VERSION 5.8 ;
BUSBITCHARS "[]" ;
DIVIDERCHAR "/" ;
UNITS
    DATABASE MICRONS 1000 ;
END UNITS

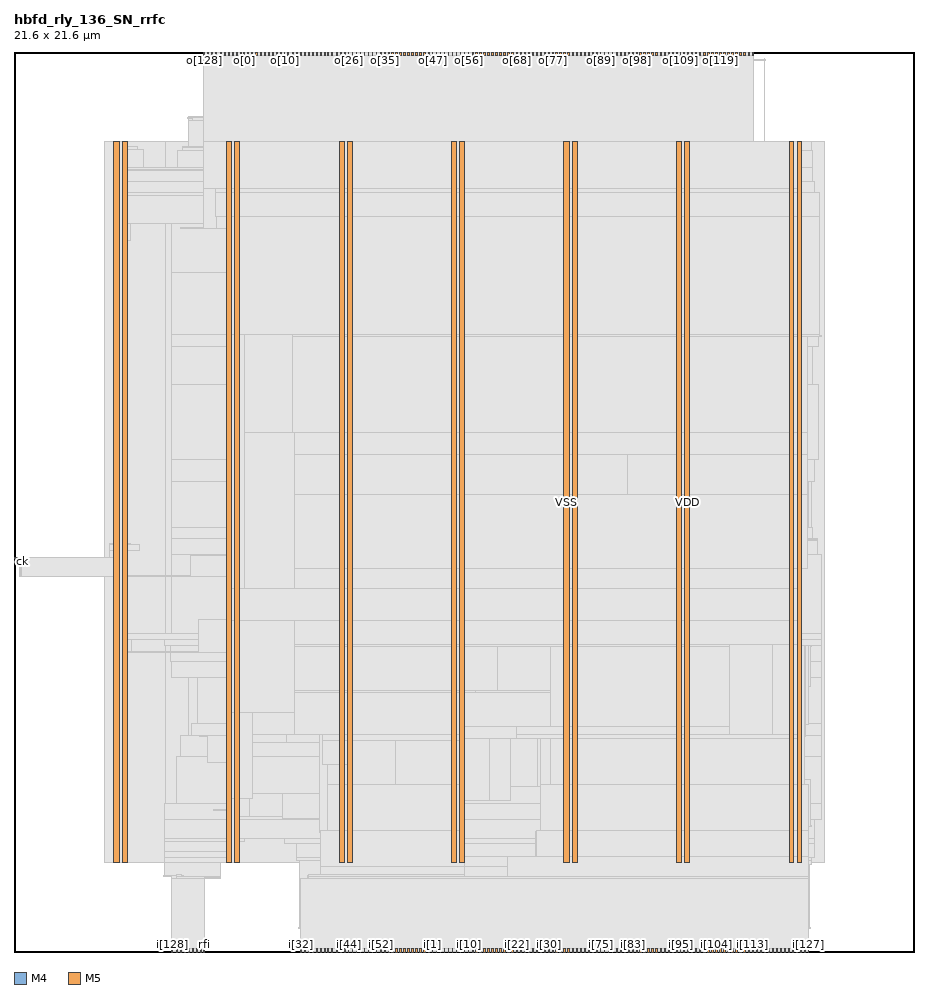
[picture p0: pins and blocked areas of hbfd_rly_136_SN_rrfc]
MACRO hbfd_rly_136_SN_rrfc
  FOREIGN hbfd_rly_136_SN_rrfc 0 0 ;
  CLASS BLOCK ;
  SIZE 21.6 BY 21.6 ;
  PIN ck
    DIRECTION INPUT ;
    USE SIGNAL ;
    PORT
      LAYER M4 ;
        RECT  0 9.36 0.084 9.384 ;
    END
  END ck
  PIN i[0]
    DIRECTION INPUT ;
    USE SIGNAL ;
    PORT
      LAYER M5 ;
        RECT  9.936 0 9.96 0.084 ;
    END
  END i[0]
  PIN i[100]
    DIRECTION INPUT ;
    USE SIGNAL ;
    PORT
      LAYER M5 ;
        RECT  16.464 0 16.488 0.084 ;
    END
  END i[100]
  PIN i[101]
    DIRECTION INPUT ;
    USE SIGNAL ;
    PORT
      LAYER M5 ;
        RECT  16.56 0 16.584 0.084 ;
    END
  END i[101]
  PIN i[102]
    DIRECTION INPUT ;
    USE SIGNAL ;
    PORT
      LAYER M5 ;
        RECT  16.656 0 16.68 0.084 ;
    END
  END i[102]
  PIN i[103]
    DIRECTION INPUT ;
    USE SIGNAL ;
    PORT
      LAYER M5 ;
        RECT  16.752 0 16.776 0.084 ;
    END
  END i[103]
  PIN i[104]
    DIRECTION INPUT ;
    USE SIGNAL ;
    PORT
      LAYER M5 ;
        RECT  16.848 0 16.872 0.084 ;
    END
  END i[104]
  PIN i[105]
    DIRECTION INPUT ;
    USE SIGNAL ;
    PORT
      LAYER M5 ;
        RECT  16.944 0 16.968 0.084 ;
    END
  END i[105]
  PIN i[106]
    DIRECTION INPUT ;
    USE SIGNAL ;
    PORT
      LAYER M5 ;
        RECT  17.04 0 17.064 0.084 ;
    END
  END i[106]
  PIN i[107]
    DIRECTION INPUT ;
    USE SIGNAL ;
    PORT
      LAYER M5 ;
        RECT  17.136 0 17.16 0.084 ;
    END
  END i[107]
  PIN i[108]
    DIRECTION INPUT ;
    USE SIGNAL ;
    PORT
      LAYER M5 ;
        RECT  17.232 0 17.256 0.084 ;
    END
  END i[108]
  PIN i[109]
    DIRECTION INPUT ;
    USE SIGNAL ;
    PORT
      LAYER M5 ;
        RECT  17.328 0 17.352 0.084 ;
    END
  END i[109]
  PIN i[10]
    DIRECTION INPUT ;
    USE SIGNAL ;
    PORT
      LAYER M5 ;
        RECT  10.896 0 10.92 0.084 ;
    END
  END i[10]
  PIN i[110]
    DIRECTION INPUT ;
    USE SIGNAL ;
    PORT
      LAYER M5 ;
        RECT  17.424 0 17.448 0.084 ;
    END
  END i[110]
  PIN i[111]
    DIRECTION INPUT ;
    USE SIGNAL ;
    PORT
      LAYER M5 ;
        RECT  17.52 0 17.544 0.084 ;
    END
  END i[111]
  PIN i[112]
    DIRECTION INPUT ;
    USE SIGNAL ;
    PORT
      LAYER M5 ;
        RECT  17.616 0 17.64 0.084 ;
    END
  END i[112]
  PIN i[113]
    DIRECTION INPUT ;
    USE SIGNAL ;
    PORT
      LAYER M5 ;
        RECT  17.712 0 17.736 0.084 ;
    END
  END i[113]
  PIN i[114]
    DIRECTION INPUT ;
    USE SIGNAL ;
    PORT
      LAYER M5 ;
        RECT  17.808 0 17.832 0.084 ;
    END
  END i[114]
  PIN i[115]
    DIRECTION INPUT ;
    USE SIGNAL ;
    PORT
      LAYER M5 ;
        RECT  17.904 0 17.928 0.084 ;
    END
  END i[115]
  PIN i[116]
    DIRECTION INPUT ;
    USE SIGNAL ;
    PORT
      LAYER M5 ;
        RECT  18 0 18.024 0.084 ;
    END
  END i[116]
  PIN i[117]
    DIRECTION INPUT ;
    USE SIGNAL ;
    PORT
      LAYER M5 ;
        RECT  18.096 0 18.12 0.084 ;
    END
  END i[117]
  PIN i[118]
    DIRECTION INPUT ;
    USE SIGNAL ;
    PORT
      LAYER M5 ;
        RECT  18.192 0 18.216 0.084 ;
    END
  END i[118]
  PIN i[119]
    DIRECTION INPUT ;
    USE SIGNAL ;
    PORT
      LAYER M5 ;
        RECT  18.288 0 18.312 0.084 ;
    END
  END i[119]
  PIN i[11]
    DIRECTION INPUT ;
    USE SIGNAL ;
    PORT
      LAYER M5 ;
        RECT  10.992 0 11.016 0.084 ;
    END
  END i[11]
  PIN i[120]
    DIRECTION INPUT ;
    USE SIGNAL ;
    PORT
      LAYER M5 ;
        RECT  18.384 0 18.408 0.084 ;
    END
  END i[120]
  PIN i[121]
    DIRECTION INPUT ;
    USE SIGNAL ;
    PORT
      LAYER M5 ;
        RECT  18.48 0 18.504 0.084 ;
    END
  END i[121]
  PIN i[122]
    DIRECTION INPUT ;
    USE SIGNAL ;
    PORT
      LAYER M5 ;
        RECT  18.576 0 18.6 0.084 ;
    END
  END i[122]
  PIN i[123]
    DIRECTION INPUT ;
    USE SIGNAL ;
    PORT
      LAYER M5 ;
        RECT  18.672 0 18.696 0.084 ;
    END
  END i[123]
  PIN i[124]
    DIRECTION INPUT ;
    USE SIGNAL ;
    PORT
      LAYER M5 ;
        RECT  18.768 0 18.792 0.084 ;
    END
  END i[124]
  PIN i[125]
    DIRECTION INPUT ;
    USE SIGNAL ;
    PORT
      LAYER M5 ;
        RECT  18.864 0 18.888 0.084 ;
    END
  END i[125]
  PIN i[126]
    DIRECTION INPUT ;
    USE SIGNAL ;
    PORT
      LAYER M5 ;
        RECT  18.96 0 18.984 0.084 ;
    END
  END i[126]
  PIN i[127]
    DIRECTION INPUT ;
    USE SIGNAL ;
    PORT
      LAYER M5 ;
        RECT  19.056 0 19.08 0.084 ;
    END
  END i[127]
  PIN i[128]
    DIRECTION INPUT ;
    USE SIGNAL ;
    PORT
      LAYER M5 ;
        RECT  3.792 0 3.816 0.084 ;
    END
  END i[128]
  PIN i[129]
    DIRECTION INPUT ;
    USE SIGNAL ;
    PORT
      LAYER M5 ;
        RECT  3.888 0 3.912 0.084 ;
    END
  END i[129]
  PIN i[12]
    DIRECTION INPUT ;
    USE SIGNAL ;
    PORT
      LAYER M5 ;
        RECT  11.088 0 11.112 0.084 ;
    END
  END i[12]
  PIN i[130]
    DIRECTION INPUT ;
    USE SIGNAL ;
    PORT
      LAYER M5 ;
        RECT  3.984 0 4.008 0.084 ;
    END
  END i[130]
  PIN i[131]
    DIRECTION INPUT ;
    USE SIGNAL ;
    PORT
      LAYER M5 ;
        RECT  4.08 0 4.104 0.084 ;
    END
  END i[131]
  PIN i[132]
    DIRECTION INPUT ;
    USE SIGNAL ;
    PORT
      LAYER M5 ;
        RECT  4.176 0 4.2 0.084 ;
    END
  END i[132]
  PIN i[133]
    DIRECTION INPUT ;
    USE SIGNAL ;
    PORT
      LAYER M5 ;
        RECT  4.272 0 4.296 0.084 ;
    END
  END i[133]
  PIN i[134]
    DIRECTION INPUT ;
    USE SIGNAL ;
    PORT
      LAYER M5 ;
        RECT  4.368 0 4.392 0.084 ;
    END
  END i[134]
  PIN i[135]
    DIRECTION INPUT ;
    USE SIGNAL ;
    PORT
      LAYER M5 ;
        RECT  4.464 0 4.488 0.084 ;
    END
  END i[135]
  PIN i[13]
    DIRECTION INPUT ;
    USE SIGNAL ;
    PORT
      LAYER M5 ;
        RECT  11.184 0 11.208 0.084 ;
    END
  END i[13]
  PIN i[14]
    DIRECTION INPUT ;
    USE SIGNAL ;
    PORT
      LAYER M5 ;
        RECT  11.28 0 11.304 0.084 ;
    END
  END i[14]
  PIN i[15]
    DIRECTION INPUT ;
    USE SIGNAL ;
    PORT
      LAYER M5 ;
        RECT  11.376 0 11.4 0.084 ;
    END
  END i[15]
  PIN i[16]
    DIRECTION INPUT ;
    USE SIGNAL ;
    PORT
      LAYER M5 ;
        RECT  11.472 0 11.496 0.084 ;
    END
  END i[16]
  PIN i[17]
    DIRECTION INPUT ;
    USE SIGNAL ;
    PORT
      LAYER M5 ;
        RECT  11.568 0 11.592 0.084 ;
    END
  END i[17]
  PIN i[18]
    DIRECTION INPUT ;
    USE SIGNAL ;
    PORT
      LAYER M5 ;
        RECT  11.664 0 11.688 0.084 ;
    END
  END i[18]
  PIN i[19]
    DIRECTION INPUT ;
    USE SIGNAL ;
    PORT
      LAYER M5 ;
        RECT  11.76 0 11.784 0.084 ;
    END
  END i[19]
  PIN i[1]
    DIRECTION INPUT ;
    USE SIGNAL ;
    PORT
      LAYER M5 ;
        RECT  10.032 0 10.056 0.084 ;
    END
  END i[1]
  PIN i[20]
    DIRECTION INPUT ;
    USE SIGNAL ;
    PORT
      LAYER M5 ;
        RECT  11.856 0 11.88 0.084 ;
    END
  END i[20]
  PIN i[21]
    DIRECTION INPUT ;
    USE SIGNAL ;
    PORT
      LAYER M5 ;
        RECT  11.952 0 11.976 0.084 ;
    END
  END i[21]
  PIN i[22]
    DIRECTION INPUT ;
    USE SIGNAL ;
    PORT
      LAYER M5 ;
        RECT  12.048 0 12.072 0.084 ;
    END
  END i[22]
  PIN i[23]
    DIRECTION INPUT ;
    USE SIGNAL ;
    PORT
      LAYER M5 ;
        RECT  12.144 0 12.168 0.084 ;
    END
  END i[23]
  PIN i[24]
    DIRECTION INPUT ;
    USE SIGNAL ;
    PORT
      LAYER M5 ;
        RECT  12.24 0 12.264 0.084 ;
    END
  END i[24]
  PIN i[25]
    DIRECTION INPUT ;
    USE SIGNAL ;
    PORT
      LAYER M5 ;
        RECT  12.336 0 12.36 0.084 ;
    END
  END i[25]
  PIN i[26]
    DIRECTION INPUT ;
    USE SIGNAL ;
    PORT
      LAYER M5 ;
        RECT  12.432 0 12.456 0.084 ;
    END
  END i[26]
  PIN i[27]
    DIRECTION INPUT ;
    USE SIGNAL ;
    PORT
      LAYER M5 ;
        RECT  12.528 0 12.552 0.084 ;
    END
  END i[27]
  PIN i[28]
    DIRECTION INPUT ;
    USE SIGNAL ;
    PORT
      LAYER M5 ;
        RECT  12.624 0 12.648 0.084 ;
    END
  END i[28]
  PIN i[29]
    DIRECTION INPUT ;
    USE SIGNAL ;
    PORT
      LAYER M5 ;
        RECT  12.72 0 12.744 0.084 ;
    END
  END i[29]
  PIN i[2]
    DIRECTION INPUT ;
    USE SIGNAL ;
    PORT
      LAYER M5 ;
        RECT  10.128 0 10.152 0.084 ;
    END
  END i[2]
  PIN i[30]
    DIRECTION INPUT ;
    USE SIGNAL ;
    PORT
      LAYER M5 ;
        RECT  12.816 0 12.84 0.084 ;
    END
  END i[30]
  PIN i[31]
    DIRECTION INPUT ;
    USE SIGNAL ;
    PORT
      LAYER M5 ;
        RECT  12.912 0 12.936 0.084 ;
    END
  END i[31]
  PIN i[32]
    DIRECTION INPUT ;
    USE SIGNAL ;
    PORT
      LAYER M5 ;
        RECT  6.864 0 6.888 0.084 ;
    END
  END i[32]
  PIN i[33]
    DIRECTION INPUT ;
    USE SIGNAL ;
    PORT
      LAYER M5 ;
        RECT  6.96 0 6.984 0.084 ;
    END
  END i[33]
  PIN i[34]
    DIRECTION INPUT ;
    USE SIGNAL ;
    PORT
      LAYER M5 ;
        RECT  7.056 0 7.08 0.084 ;
    END
  END i[34]
  PIN i[35]
    DIRECTION INPUT ;
    USE SIGNAL ;
    PORT
      LAYER M5 ;
        RECT  7.152 0 7.176 0.084 ;
    END
  END i[35]
  PIN i[36]
    DIRECTION INPUT ;
    USE SIGNAL ;
    PORT
      LAYER M5 ;
        RECT  7.248 0 7.272 0.084 ;
    END
  END i[36]
  PIN i[37]
    DIRECTION INPUT ;
    USE SIGNAL ;
    PORT
      LAYER M5 ;
        RECT  7.344 0 7.368 0.084 ;
    END
  END i[37]
  PIN i[38]
    DIRECTION INPUT ;
    USE SIGNAL ;
    PORT
      LAYER M5 ;
        RECT  7.44 0 7.464 0.084 ;
    END
  END i[38]
  PIN i[39]
    DIRECTION INPUT ;
    USE SIGNAL ;
    PORT
      LAYER M5 ;
        RECT  7.536 0 7.56 0.084 ;
    END
  END i[39]
  PIN i[3]
    DIRECTION INPUT ;
    USE SIGNAL ;
    PORT
      LAYER M5 ;
        RECT  10.224 0 10.248 0.084 ;
    END
  END i[3]
  PIN i[40]
    DIRECTION INPUT ;
    USE SIGNAL ;
    PORT
      LAYER M5 ;
        RECT  7.632 0 7.656 0.084 ;
    END
  END i[40]
  PIN i[41]
    DIRECTION INPUT ;
    USE SIGNAL ;
    PORT
      LAYER M5 ;
        RECT  7.728 0 7.752 0.084 ;
    END
  END i[41]
  PIN i[42]
    DIRECTION INPUT ;
    USE SIGNAL ;
    PORT
      LAYER M5 ;
        RECT  7.824 0 7.848 0.084 ;
    END
  END i[42]
  PIN i[43]
    DIRECTION INPUT ;
    USE SIGNAL ;
    PORT
      LAYER M5 ;
        RECT  7.92 0 7.944 0.084 ;
    END
  END i[43]
  PIN i[44]
    DIRECTION INPUT ;
    USE SIGNAL ;
    PORT
      LAYER M5 ;
        RECT  8.016 0 8.04 0.084 ;
    END
  END i[44]
  PIN i[45]
    DIRECTION INPUT ;
    USE SIGNAL ;
    PORT
      LAYER M5 ;
        RECT  8.112 0 8.136 0.084 ;
    END
  END i[45]
  PIN i[46]
    DIRECTION INPUT ;
    USE SIGNAL ;
    PORT
      LAYER M5 ;
        RECT  8.208 0 8.232 0.084 ;
    END
  END i[46]
  PIN i[47]
    DIRECTION INPUT ;
    USE SIGNAL ;
    PORT
      LAYER M5 ;
        RECT  8.304 0 8.328 0.084 ;
    END
  END i[47]
  PIN i[48]
    DIRECTION INPUT ;
    USE SIGNAL ;
    PORT
      LAYER M5 ;
        RECT  8.4 0 8.424 0.084 ;
    END
  END i[48]
  PIN i[49]
    DIRECTION INPUT ;
    USE SIGNAL ;
    PORT
      LAYER M5 ;
        RECT  8.496 0 8.52 0.084 ;
    END
  END i[49]
  PIN i[4]
    DIRECTION INPUT ;
    USE SIGNAL ;
    PORT
      LAYER M5 ;
        RECT  10.32 0 10.344 0.084 ;
    END
  END i[4]
  PIN i[50]
    DIRECTION INPUT ;
    USE SIGNAL ;
    PORT
      LAYER M5 ;
        RECT  8.592 0 8.616 0.084 ;
    END
  END i[50]
  PIN i[51]
    DIRECTION INPUT ;
    USE SIGNAL ;
    PORT
      LAYER M5 ;
        RECT  8.688 0 8.712 0.084 ;
    END
  END i[51]
  PIN i[52]
    DIRECTION INPUT ;
    USE SIGNAL ;
    PORT
      LAYER M5 ;
        RECT  8.784 0 8.808 0.084 ;
    END
  END i[52]
  PIN i[53]
    DIRECTION INPUT ;
    USE SIGNAL ;
    PORT
      LAYER M5 ;
        RECT  8.88 0 8.904 0.084 ;
    END
  END i[53]
  PIN i[54]
    DIRECTION INPUT ;
    USE SIGNAL ;
    PORT
      LAYER M5 ;
        RECT  8.976 0 9 0.084 ;
    END
  END i[54]
  PIN i[55]
    DIRECTION INPUT ;
    USE SIGNAL ;
    PORT
      LAYER M5 ;
        RECT  9.072 0 9.096 0.084 ;
    END
  END i[55]
  PIN i[56]
    DIRECTION INPUT ;
    USE SIGNAL ;
    PORT
      LAYER M5 ;
        RECT  9.168 0 9.192 0.084 ;
    END
  END i[56]
  PIN i[57]
    DIRECTION INPUT ;
    USE SIGNAL ;
    PORT
      LAYER M5 ;
        RECT  9.264 0 9.288 0.084 ;
    END
  END i[57]
  PIN i[58]
    DIRECTION INPUT ;
    USE SIGNAL ;
    PORT
      LAYER M5 ;
        RECT  9.36 0 9.384 0.084 ;
    END
  END i[58]
  PIN i[59]
    DIRECTION INPUT ;
    USE SIGNAL ;
    PORT
      LAYER M5 ;
        RECT  9.456 0 9.48 0.084 ;
    END
  END i[59]
  PIN i[5]
    DIRECTION INPUT ;
    USE SIGNAL ;
    PORT
      LAYER M5 ;
        RECT  10.416 0 10.44 0.084 ;
    END
  END i[5]
  PIN i[60]
    DIRECTION INPUT ;
    USE SIGNAL ;
    PORT
      LAYER M5 ;
        RECT  9.552 0 9.576 0.084 ;
    END
  END i[60]
  PIN i[61]
    DIRECTION INPUT ;
    USE SIGNAL ;
    PORT
      LAYER M5 ;
        RECT  9.648 0 9.672 0.084 ;
    END
  END i[61]
  PIN i[62]
    DIRECTION INPUT ;
    USE SIGNAL ;
    PORT
      LAYER M5 ;
        RECT  9.744 0 9.768 0.084 ;
    END
  END i[62]
  PIN i[63]
    DIRECTION INPUT ;
    USE SIGNAL ;
    PORT
      LAYER M5 ;
        RECT  9.84 0 9.864 0.084 ;
    END
  END i[63]
  PIN i[64]
    DIRECTION INPUT ;
    USE SIGNAL ;
    PORT
      LAYER M5 ;
        RECT  13.008 0 13.032 0.084 ;
    END
  END i[64]
  PIN i[65]
    DIRECTION INPUT ;
    USE SIGNAL ;
    PORT
      LAYER M5 ;
        RECT  13.104 0 13.128 0.084 ;
    END
  END i[65]
  PIN i[66]
    DIRECTION INPUT ;
    USE SIGNAL ;
    PORT
      LAYER M5 ;
        RECT  13.2 0 13.224 0.084 ;
    END
  END i[66]
  PIN i[67]
    DIRECTION INPUT ;
    USE SIGNAL ;
    PORT
      LAYER M5 ;
        RECT  13.296 0 13.32 0.084 ;
    END
  END i[67]
  PIN i[68]
    DIRECTION INPUT ;
    USE SIGNAL ;
    PORT
      LAYER M5 ;
        RECT  13.392 0 13.416 0.084 ;
    END
  END i[68]
  PIN i[69]
    DIRECTION INPUT ;
    USE SIGNAL ;
    PORT
      LAYER M5 ;
        RECT  13.488 0 13.512 0.084 ;
    END
  END i[69]
  PIN i[6]
    DIRECTION INPUT ;
    USE SIGNAL ;
    PORT
      LAYER M5 ;
        RECT  10.512 0 10.536 0.084 ;
    END
  END i[6]
  PIN i[70]
    DIRECTION INPUT ;
    USE SIGNAL ;
    PORT
      LAYER M5 ;
        RECT  13.584 0 13.608 0.084 ;
    END
  END i[70]
  PIN i[71]
    DIRECTION INPUT ;
    USE SIGNAL ;
    PORT
      LAYER M5 ;
        RECT  13.68 0 13.704 0.084 ;
    END
  END i[71]
  PIN i[72]
    DIRECTION INPUT ;
    USE SIGNAL ;
    PORT
      LAYER M5 ;
        RECT  13.776 0 13.8 0.084 ;
    END
  END i[72]
  PIN i[73]
    DIRECTION INPUT ;
    USE SIGNAL ;
    PORT
      LAYER M5 ;
        RECT  13.872 0 13.896 0.084 ;
    END
  END i[73]
  PIN i[74]
    DIRECTION INPUT ;
    USE SIGNAL ;
    PORT
      LAYER M5 ;
        RECT  13.968 0 13.992 0.084 ;
    END
  END i[74]
  PIN i[75]
    DIRECTION INPUT ;
    USE SIGNAL ;
    PORT
      LAYER M5 ;
        RECT  14.064 0 14.088 0.084 ;
    END
  END i[75]
  PIN i[76]
    DIRECTION INPUT ;
    USE SIGNAL ;
    PORT
      LAYER M5 ;
        RECT  14.16 0 14.184 0.084 ;
    END
  END i[76]
  PIN i[77]
    DIRECTION INPUT ;
    USE SIGNAL ;
    PORT
      LAYER M5 ;
        RECT  14.256 0 14.28 0.084 ;
    END
  END i[77]
  PIN i[78]
    DIRECTION INPUT ;
    USE SIGNAL ;
    PORT
      LAYER M5 ;
        RECT  14.352 0 14.376 0.084 ;
    END
  END i[78]
  PIN i[79]
    DIRECTION INPUT ;
    USE SIGNAL ;
    PORT
      LAYER M5 ;
        RECT  14.448 0 14.472 0.084 ;
    END
  END i[79]
  PIN i[7]
    DIRECTION INPUT ;
    USE SIGNAL ;
    PORT
      LAYER M5 ;
        RECT  10.608 0 10.632 0.084 ;
    END
  END i[7]
  PIN i[80]
    DIRECTION INPUT ;
    USE SIGNAL ;
    PORT
      LAYER M5 ;
        RECT  14.544 0 14.568 0.084 ;
    END
  END i[80]
  PIN i[81]
    DIRECTION INPUT ;
    USE SIGNAL ;
    PORT
      LAYER M5 ;
        RECT  14.64 0 14.664 0.084 ;
    END
  END i[81]
  PIN i[82]
    DIRECTION INPUT ;
    USE SIGNAL ;
    PORT
      LAYER M5 ;
        RECT  14.736 0 14.76 0.084 ;
    END
  END i[82]
  PIN i[83]
    DIRECTION INPUT ;
    USE SIGNAL ;
    PORT
      LAYER M5 ;
        RECT  14.832 0 14.856 0.084 ;
    END
  END i[83]
  PIN i[84]
    DIRECTION INPUT ;
    USE SIGNAL ;
    PORT
      LAYER M5 ;
        RECT  14.928 0 14.952 0.084 ;
    END
  END i[84]
  PIN i[85]
    DIRECTION INPUT ;
    USE SIGNAL ;
    PORT
      LAYER M5 ;
        RECT  15.024 0 15.048 0.084 ;
    END
  END i[85]
  PIN i[86]
    DIRECTION INPUT ;
    USE SIGNAL ;
    PORT
      LAYER M5 ;
        RECT  15.12 0 15.144 0.084 ;
    END
  END i[86]
  PIN i[87]
    DIRECTION INPUT ;
    USE SIGNAL ;
    PORT
      LAYER M5 ;
        RECT  15.216 0 15.24 0.084 ;
    END
  END i[87]
  PIN i[88]
    DIRECTION INPUT ;
    USE SIGNAL ;
    PORT
      LAYER M5 ;
        RECT  15.312 0 15.336 0.084 ;
    END
  END i[88]
  PIN i[89]
    DIRECTION INPUT ;
    USE SIGNAL ;
    PORT
      LAYER M5 ;
        RECT  15.408 0 15.432 0.084 ;
    END
  END i[89]
  PIN i[8]
    DIRECTION INPUT ;
    USE SIGNAL ;
    PORT
      LAYER M5 ;
        RECT  10.704 0 10.728 0.084 ;
    END
  END i[8]
  PIN i[90]
    DIRECTION INPUT ;
    USE SIGNAL ;
    PORT
      LAYER M5 ;
        RECT  15.504 0 15.528 0.084 ;
    END
  END i[90]
  PIN i[91]
    DIRECTION INPUT ;
    USE SIGNAL ;
    PORT
      LAYER M5 ;
        RECT  15.6 0 15.624 0.084 ;
    END
  END i[91]
  PIN i[92]
    DIRECTION INPUT ;
    USE SIGNAL ;
    PORT
      LAYER M5 ;
        RECT  15.696 0 15.72 0.084 ;
    END
  END i[92]
  PIN i[93]
    DIRECTION INPUT ;
    USE SIGNAL ;
    PORT
      LAYER M5 ;
        RECT  15.792 0 15.816 0.084 ;
    END
  END i[93]
  PIN i[94]
    DIRECTION INPUT ;
    USE SIGNAL ;
    PORT
      LAYER M5 ;
        RECT  15.888 0 15.912 0.084 ;
    END
  END i[94]
  PIN i[95]
    DIRECTION INPUT ;
    USE SIGNAL ;
    PORT
      LAYER M5 ;
        RECT  15.984 0 16.008 0.084 ;
    END
  END i[95]
  PIN i[96]
    DIRECTION INPUT ;
    USE SIGNAL ;
    PORT
      LAYER M5 ;
        RECT  16.08 0 16.104 0.084 ;
    END
  END i[96]
  PIN i[97]
    DIRECTION INPUT ;
    USE SIGNAL ;
    PORT
      LAYER M5 ;
        RECT  16.176 0 16.2 0.084 ;
    END
  END i[97]
  PIN i[98]
    DIRECTION INPUT ;
    USE SIGNAL ;
    PORT
      LAYER M5 ;
        RECT  16.272 0 16.296 0.084 ;
    END
  END i[98]
  PIN i[99]
    DIRECTION INPUT ;
    USE SIGNAL ;
    PORT
      LAYER M5 ;
        RECT  16.368 0 16.392 0.084 ;
    END
  END i[99]
  PIN i[9]
    DIRECTION INPUT ;
    USE SIGNAL ;
    PORT
      LAYER M5 ;
        RECT  10.8 0 10.824 0.084 ;
    END
  END i[9]
  PIN o[0]
    DIRECTION OUTPUT ;
    USE SIGNAL ;
    PORT
      LAYER M5 ;
        RECT  5.52 21.516 5.544 21.6 ;
    END
  END o[0]
  PIN o[100]
    DIRECTION OUTPUT ;
    USE SIGNAL ;
    PORT
      LAYER M5 ;
        RECT  15.12 21.516 15.144 21.6 ;
    END
  END o[100]
  PIN o[101]
    DIRECTION OUTPUT ;
    USE SIGNAL ;
    PORT
      LAYER M5 ;
        RECT  15.216 21.516 15.24 21.6 ;
    END
  END o[101]
  PIN o[102]
    DIRECTION OUTPUT ;
    USE SIGNAL ;
    PORT
      LAYER M5 ;
        RECT  15.312 21.516 15.336 21.6 ;
    END
  END o[102]
  PIN o[103]
    DIRECTION OUTPUT ;
    USE SIGNAL ;
    PORT
      LAYER M5 ;
        RECT  15.408 21.516 15.432 21.6 ;
    END
  END o[103]
  PIN o[104]
    DIRECTION OUTPUT ;
    USE SIGNAL ;
    PORT
      LAYER M5 ;
        RECT  15.504 21.516 15.528 21.6 ;
    END
  END o[104]
  PIN o[105]
    DIRECTION OUTPUT ;
    USE SIGNAL ;
    PORT
      LAYER M5 ;
        RECT  15.6 21.516 15.624 21.6 ;
    END
  END o[105]
  PIN o[106]
    DIRECTION OUTPUT ;
    USE SIGNAL ;
    PORT
      LAYER M5 ;
        RECT  15.696 21.516 15.72 21.6 ;
    END
  END o[106]
  PIN o[107]
    DIRECTION OUTPUT ;
    USE SIGNAL ;
    PORT
      LAYER M5 ;
        RECT  15.792 21.516 15.816 21.6 ;
    END
  END o[107]
  PIN o[108]
    DIRECTION OUTPUT ;
    USE SIGNAL ;
    PORT
      LAYER M5 ;
        RECT  15.888 21.516 15.912 21.6 ;
    END
  END o[108]
  PIN o[109]
    DIRECTION OUTPUT ;
    USE SIGNAL ;
    PORT
      LAYER M5 ;
        RECT  15.984 21.516 16.008 21.6 ;
    END
  END o[109]
  PIN o[10]
    DIRECTION OUTPUT ;
    USE SIGNAL ;
    PORT
      LAYER M5 ;
        RECT  6.48 21.516 6.504 21.6 ;
    END
  END o[10]
  PIN o[110]
    DIRECTION OUTPUT ;
    USE SIGNAL ;
    PORT
      LAYER M5 ;
        RECT  16.08 21.516 16.104 21.6 ;
    END
  END o[110]
  PIN o[111]
    DIRECTION OUTPUT ;
    USE SIGNAL ;
    PORT
      LAYER M5 ;
        RECT  16.176 21.516 16.2 21.6 ;
    END
  END o[111]
  PIN o[112]
    DIRECTION OUTPUT ;
    USE SIGNAL ;
    PORT
      LAYER M5 ;
        RECT  16.272 21.516 16.296 21.6 ;
    END
  END o[112]
  PIN o[113]
    DIRECTION OUTPUT ;
    USE SIGNAL ;
    PORT
      LAYER M5 ;
        RECT  16.368 21.516 16.392 21.6 ;
    END
  END o[113]
  PIN o[114]
    DIRECTION OUTPUT ;
    USE SIGNAL ;
    PORT
      LAYER M5 ;
        RECT  16.464 21.516 16.488 21.6 ;
    END
  END o[114]
  PIN o[115]
    DIRECTION OUTPUT ;
    USE SIGNAL ;
    PORT
      LAYER M5 ;
        RECT  16.56 21.516 16.584 21.6 ;
    END
  END o[115]
  PIN o[116]
    DIRECTION OUTPUT ;
    USE SIGNAL ;
    PORT
      LAYER M5 ;
        RECT  16.656 21.516 16.68 21.6 ;
    END
  END o[116]
  PIN o[117]
    DIRECTION OUTPUT ;
    USE SIGNAL ;
    PORT
      LAYER M5 ;
        RECT  16.752 21.516 16.776 21.6 ;
    END
  END o[117]
  PIN o[118]
    DIRECTION OUTPUT ;
    USE SIGNAL ;
    PORT
      LAYER M5 ;
        RECT  16.848 21.516 16.872 21.6 ;
    END
  END o[118]
  PIN o[119]
    DIRECTION OUTPUT ;
    USE SIGNAL ;
    PORT
      LAYER M5 ;
        RECT  16.944 21.516 16.968 21.6 ;
    END
  END o[119]
  PIN o[11]
    DIRECTION OUTPUT ;
    USE SIGNAL ;
    PORT
      LAYER M5 ;
        RECT  6.576 21.516 6.6 21.6 ;
    END
  END o[11]
  PIN o[120]
    DIRECTION OUTPUT ;
    USE SIGNAL ;
    PORT
      LAYER M5 ;
        RECT  17.04 21.516 17.064 21.6 ;
    END
  END o[120]
  PIN o[121]
    DIRECTION OUTPUT ;
    USE SIGNAL ;
    PORT
      LAYER M5 ;
        RECT  17.136 21.516 17.16 21.6 ;
    END
  END o[121]
  PIN o[122]
    DIRECTION OUTPUT ;
    USE SIGNAL ;
    PORT
      LAYER M5 ;
        RECT  17.232 21.516 17.256 21.6 ;
    END
  END o[122]
  PIN o[123]
    DIRECTION OUTPUT ;
    USE SIGNAL ;
    PORT
      LAYER M5 ;
        RECT  17.328 21.516 17.352 21.6 ;
    END
  END o[123]
  PIN o[124]
    DIRECTION OUTPUT ;
    USE SIGNAL ;
    PORT
      LAYER M5 ;
        RECT  17.424 21.516 17.448 21.6 ;
    END
  END o[124]
  PIN o[125]
    DIRECTION OUTPUT ;
    USE SIGNAL ;
    PORT
      LAYER M5 ;
        RECT  17.52 21.516 17.544 21.6 ;
    END
  END o[125]
  PIN o[126]
    DIRECTION OUTPUT ;
    USE SIGNAL ;
    PORT
      LAYER M5 ;
        RECT  17.616 21.516 17.64 21.6 ;
    END
  END o[126]
  PIN o[127]
    DIRECTION OUTPUT ;
    USE SIGNAL ;
    PORT
      LAYER M5 ;
        RECT  17.712 21.516 17.736 21.6 ;
    END
  END o[127]
  PIN o[128]
    DIRECTION OUTPUT ;
    USE SIGNAL ;
    PORT
      LAYER M5 ;
        RECT  4.56 21.516 4.584 21.6 ;
    END
  END o[128]
  PIN o[129]
    DIRECTION OUTPUT ;
    USE SIGNAL ;
    PORT
      LAYER M5 ;
        RECT  4.656 21.516 4.68 21.6 ;
    END
  END o[129]
  PIN o[12]
    DIRECTION OUTPUT ;
    USE SIGNAL ;
    PORT
      LAYER M5 ;
        RECT  6.672 21.516 6.696 21.6 ;
    END
  END o[12]
  PIN o[130]
    DIRECTION OUTPUT ;
    USE SIGNAL ;
    PORT
      LAYER M5 ;
        RECT  4.752 21.516 4.776 21.6 ;
    END
  END o[130]
  PIN o[131]
    DIRECTION OUTPUT ;
    USE SIGNAL ;
    PORT
      LAYER M5 ;
        RECT  4.848 21.516 4.872 21.6 ;
    END
  END o[131]
  PIN o[132]
    DIRECTION OUTPUT ;
    USE SIGNAL ;
    PORT
      LAYER M5 ;
        RECT  4.944 21.516 4.968 21.6 ;
    END
  END o[132]
  PIN o[133]
    DIRECTION OUTPUT ;
    USE SIGNAL ;
    PORT
      LAYER M5 ;
        RECT  5.04 21.516 5.064 21.6 ;
    END
  END o[133]
  PIN o[134]
    DIRECTION OUTPUT ;
    USE SIGNAL ;
    PORT
      LAYER M5 ;
        RECT  5.136 21.516 5.16 21.6 ;
    END
  END o[134]
  PIN o[135]
    DIRECTION OUTPUT ;
    USE SIGNAL ;
    PORT
      LAYER M5 ;
        RECT  5.232 21.516 5.256 21.6 ;
    END
  END o[135]
  PIN o[13]
    DIRECTION OUTPUT ;
    USE SIGNAL ;
    PORT
      LAYER M5 ;
        RECT  6.768 21.516 6.792 21.6 ;
    END
  END o[13]
  PIN o[14]
    DIRECTION OUTPUT ;
    USE SIGNAL ;
    PORT
      LAYER M5 ;
        RECT  6.864 21.516 6.888 21.6 ;
    END
  END o[14]
  PIN o[15]
    DIRECTION OUTPUT ;
    USE SIGNAL ;
    PORT
      LAYER M5 ;
        RECT  6.96 21.516 6.984 21.6 ;
    END
  END o[15]
  PIN o[16]
    DIRECTION OUTPUT ;
    USE SIGNAL ;
    PORT
      LAYER M5 ;
        RECT  7.056 21.516 7.08 21.6 ;
    END
  END o[16]
  PIN o[17]
    DIRECTION OUTPUT ;
    USE SIGNAL ;
    PORT
      LAYER M5 ;
        RECT  7.152 21.516 7.176 21.6 ;
    END
  END o[17]
  PIN o[18]
    DIRECTION OUTPUT ;
    USE SIGNAL ;
    PORT
      LAYER M5 ;
        RECT  7.248 21.516 7.272 21.6 ;
    END
  END o[18]
  PIN o[19]
    DIRECTION OUTPUT ;
    USE SIGNAL ;
    PORT
      LAYER M5 ;
        RECT  7.344 21.516 7.368 21.6 ;
    END
  END o[19]
  PIN o[1]
    DIRECTION OUTPUT ;
    USE SIGNAL ;
    PORT
      LAYER M5 ;
        RECT  5.616 21.516 5.64 21.6 ;
    END
  END o[1]
  PIN o[20]
    DIRECTION OUTPUT ;
    USE SIGNAL ;
    PORT
      LAYER M5 ;
        RECT  7.44 21.516 7.464 21.6 ;
    END
  END o[20]
  PIN o[21]
    DIRECTION OUTPUT ;
    USE SIGNAL ;
    PORT
      LAYER M5 ;
        RECT  7.536 21.516 7.56 21.6 ;
    END
  END o[21]
  PIN o[22]
    DIRECTION OUTPUT ;
    USE SIGNAL ;
    PORT
      LAYER M5 ;
        RECT  7.632 21.516 7.656 21.6 ;
    END
  END o[22]
  PIN o[23]
    DIRECTION OUTPUT ;
    USE SIGNAL ;
    PORT
      LAYER M5 ;
        RECT  7.728 21.516 7.752 21.6 ;
    END
  END o[23]
  PIN o[24]
    DIRECTION OUTPUT ;
    USE SIGNAL ;
    PORT
      LAYER M5 ;
        RECT  7.824 21.516 7.848 21.6 ;
    END
  END o[24]
  PIN o[25]
    DIRECTION OUTPUT ;
    USE SIGNAL ;
    PORT
      LAYER M5 ;
        RECT  7.92 21.516 7.944 21.6 ;
    END
  END o[25]
  PIN o[26]
    DIRECTION OUTPUT ;
    USE SIGNAL ;
    PORT
      LAYER M5 ;
        RECT  8.016 21.516 8.04 21.6 ;
    END
  END o[26]
  PIN o[27]
    DIRECTION OUTPUT ;
    USE SIGNAL ;
    PORT
      LAYER M5 ;
        RECT  8.112 21.516 8.136 21.6 ;
    END
  END o[27]
  PIN o[28]
    DIRECTION OUTPUT ;
    USE SIGNAL ;
    PORT
      LAYER M5 ;
        RECT  8.208 21.516 8.232 21.6 ;
    END
  END o[28]
  PIN o[29]
    DIRECTION OUTPUT ;
    USE SIGNAL ;
    PORT
      LAYER M5 ;
        RECT  8.304 21.516 8.328 21.6 ;
    END
  END o[29]
  PIN o[2]
    DIRECTION OUTPUT ;
    USE SIGNAL ;
    PORT
      LAYER M5 ;
        RECT  5.712 21.516 5.736 21.6 ;
    END
  END o[2]
  PIN o[30]
    DIRECTION OUTPUT ;
    USE SIGNAL ;
    PORT
      LAYER M5 ;
        RECT  8.4 21.516 8.424 21.6 ;
    END
  END o[30]
  PIN o[31]
    DIRECTION OUTPUT ;
    USE SIGNAL ;
    PORT
      LAYER M5 ;
        RECT  8.496 21.516 8.52 21.6 ;
    END
  END o[31]
  PIN o[32]
    DIRECTION OUTPUT ;
    USE SIGNAL ;
    PORT
      LAYER M5 ;
        RECT  8.592 21.516 8.616 21.6 ;
    END
  END o[32]
  PIN o[33]
    DIRECTION OUTPUT ;
    USE SIGNAL ;
    PORT
      LAYER M5 ;
        RECT  8.688 21.516 8.712 21.6 ;
    END
  END o[33]
  PIN o[34]
    DIRECTION OUTPUT ;
    USE SIGNAL ;
    PORT
      LAYER M5 ;
        RECT  8.784 21.516 8.808 21.6 ;
    END
  END o[34]
  PIN o[35]
    DIRECTION OUTPUT ;
    USE SIGNAL ;
    PORT
      LAYER M5 ;
        RECT  8.88 21.516 8.904 21.6 ;
    END
  END o[35]
  PIN o[36]
    DIRECTION OUTPUT ;
    USE SIGNAL ;
    PORT
      LAYER M5 ;
        RECT  8.976 21.516 9 21.6 ;
    END
  END o[36]
  PIN o[37]
    DIRECTION OUTPUT ;
    USE SIGNAL ;
    PORT
      LAYER M5 ;
        RECT  9.072 21.516 9.096 21.6 ;
    END
  END o[37]
  PIN o[38]
    DIRECTION OUTPUT ;
    USE SIGNAL ;
    PORT
      LAYER M5 ;
        RECT  9.168 21.516 9.192 21.6 ;
    END
  END o[38]
  PIN o[39]
    DIRECTION OUTPUT ;
    USE SIGNAL ;
    PORT
      LAYER M5 ;
        RECT  9.264 21.516 9.288 21.6 ;
    END
  END o[39]
  PIN o[3]
    DIRECTION OUTPUT ;
    USE SIGNAL ;
    PORT
      LAYER M5 ;
        RECT  5.808 21.516 5.832 21.6 ;
    END
  END o[3]
  PIN o[40]
    DIRECTION OUTPUT ;
    USE SIGNAL ;
    PORT
      LAYER M5 ;
        RECT  9.36 21.516 9.384 21.6 ;
    END
  END o[40]
  PIN o[41]
    DIRECTION OUTPUT ;
    USE SIGNAL ;
    PORT
      LAYER M5 ;
        RECT  9.456 21.516 9.48 21.6 ;
    END
  END o[41]
  PIN o[42]
    DIRECTION OUTPUT ;
    USE SIGNAL ;
    PORT
      LAYER M5 ;
        RECT  9.552 21.516 9.576 21.6 ;
    END
  END o[42]
  PIN o[43]
    DIRECTION OUTPUT ;
    USE SIGNAL ;
    PORT
      LAYER M5 ;
        RECT  9.648 21.516 9.672 21.6 ;
    END
  END o[43]
  PIN o[44]
    DIRECTION OUTPUT ;
    USE SIGNAL ;
    PORT
      LAYER M5 ;
        RECT  9.744 21.516 9.768 21.6 ;
    END
  END o[44]
  PIN o[45]
    DIRECTION OUTPUT ;
    USE SIGNAL ;
    PORT
      LAYER M5 ;
        RECT  9.84 21.516 9.864 21.6 ;
    END
  END o[45]
  PIN o[46]
    DIRECTION OUTPUT ;
    USE SIGNAL ;
    PORT
      LAYER M5 ;
        RECT  9.936 21.516 9.96 21.6 ;
    END
  END o[46]
  PIN o[47]
    DIRECTION OUTPUT ;
    USE SIGNAL ;
    PORT
      LAYER M5 ;
        RECT  10.032 21.516 10.056 21.6 ;
    END
  END o[47]
  PIN o[48]
    DIRECTION OUTPUT ;
    USE SIGNAL ;
    PORT
      LAYER M5 ;
        RECT  10.128 21.516 10.152 21.6 ;
    END
  END o[48]
  PIN o[49]
    DIRECTION OUTPUT ;
    USE SIGNAL ;
    PORT
      LAYER M5 ;
        RECT  10.224 21.516 10.248 21.6 ;
    END
  END o[49]
  PIN o[4]
    DIRECTION OUTPUT ;
    USE SIGNAL ;
    PORT
      LAYER M5 ;
        RECT  5.904 21.516 5.928 21.6 ;
    END
  END o[4]
  PIN o[50]
    DIRECTION OUTPUT ;
    USE SIGNAL ;
    PORT
      LAYER M5 ;
        RECT  10.32 21.516 10.344 21.6 ;
    END
  END o[50]
  PIN o[51]
    DIRECTION OUTPUT ;
    USE SIGNAL ;
    PORT
      LAYER M5 ;
        RECT  10.416 21.516 10.44 21.6 ;
    END
  END o[51]
  PIN o[52]
    DIRECTION OUTPUT ;
    USE SIGNAL ;
    PORT
      LAYER M5 ;
        RECT  10.512 21.516 10.536 21.6 ;
    END
  END o[52]
  PIN o[53]
    DIRECTION OUTPUT ;
    USE SIGNAL ;
    PORT
      LAYER M5 ;
        RECT  10.608 21.516 10.632 21.6 ;
    END
  END o[53]
  PIN o[54]
    DIRECTION OUTPUT ;
    USE SIGNAL ;
    PORT
      LAYER M5 ;
        RECT  10.704 21.516 10.728 21.6 ;
    END
  END o[54]
  PIN o[55]
    DIRECTION OUTPUT ;
    USE SIGNAL ;
    PORT
      LAYER M5 ;
        RECT  10.8 21.516 10.824 21.6 ;
    END
  END o[55]
  PIN o[56]
    DIRECTION OUTPUT ;
    USE SIGNAL ;
    PORT
      LAYER M5 ;
        RECT  10.896 21.516 10.92 21.6 ;
    END
  END o[56]
  PIN o[57]
    DIRECTION OUTPUT ;
    USE SIGNAL ;
    PORT
      LAYER M5 ;
        RECT  10.992 21.516 11.016 21.6 ;
    END
  END o[57]
  PIN o[58]
    DIRECTION OUTPUT ;
    USE SIGNAL ;
    PORT
      LAYER M5 ;
        RECT  11.088 21.516 11.112 21.6 ;
    END
  END o[58]
  PIN o[59]
    DIRECTION OUTPUT ;
    USE SIGNAL ;
    PORT
      LAYER M5 ;
        RECT  11.184 21.516 11.208 21.6 ;
    END
  END o[59]
  PIN o[5]
    DIRECTION OUTPUT ;
    USE SIGNAL ;
    PORT
      LAYER M5 ;
        RECT  6 21.516 6.024 21.6 ;
    END
  END o[5]
  PIN o[60]
    DIRECTION OUTPUT ;
    USE SIGNAL ;
    PORT
      LAYER M5 ;
        RECT  11.28 21.516 11.304 21.6 ;
    END
  END o[60]
  PIN o[61]
    DIRECTION OUTPUT ;
    USE SIGNAL ;
    PORT
      LAYER M5 ;
        RECT  11.376 21.516 11.4 21.6 ;
    END
  END o[61]
  PIN o[62]
    DIRECTION OUTPUT ;
    USE SIGNAL ;
    PORT
      LAYER M5 ;
        RECT  11.472 21.516 11.496 21.6 ;
    END
  END o[62]
  PIN o[63]
    DIRECTION OUTPUT ;
    USE SIGNAL ;
    PORT
      LAYER M5 ;
        RECT  11.568 21.516 11.592 21.6 ;
    END
  END o[63]
  PIN o[64]
    DIRECTION OUTPUT ;
    USE SIGNAL ;
    PORT
      LAYER M5 ;
        RECT  11.664 21.516 11.688 21.6 ;
    END
  END o[64]
  PIN o[65]
    DIRECTION OUTPUT ;
    USE SIGNAL ;
    PORT
      LAYER M5 ;
        RECT  11.76 21.516 11.784 21.6 ;
    END
  END o[65]
  PIN o[66]
    DIRECTION OUTPUT ;
    USE SIGNAL ;
    PORT
      LAYER M5 ;
        RECT  11.856 21.516 11.88 21.6 ;
    END
  END o[66]
  PIN o[67]
    DIRECTION OUTPUT ;
    USE SIGNAL ;
    PORT
      LAYER M5 ;
        RECT  11.952 21.516 11.976 21.6 ;
    END
  END o[67]
  PIN o[68]
    DIRECTION OUTPUT ;
    USE SIGNAL ;
    PORT
      LAYER M5 ;
        RECT  12.048 21.516 12.072 21.6 ;
    END
  END o[68]
  PIN o[69]
    DIRECTION OUTPUT ;
    USE SIGNAL ;
    PORT
      LAYER M5 ;
        RECT  12.144 21.516 12.168 21.6 ;
    END
  END o[69]
  PIN o[6]
    DIRECTION OUTPUT ;
    USE SIGNAL ;
    PORT
      LAYER M5 ;
        RECT  6.096 21.516 6.12 21.6 ;
    END
  END o[6]
  PIN o[70]
    DIRECTION OUTPUT ;
    USE SIGNAL ;
    PORT
      LAYER M5 ;
        RECT  12.24 21.516 12.264 21.6 ;
    END
  END o[70]
  PIN o[71]
    DIRECTION OUTPUT ;
    USE SIGNAL ;
    PORT
      LAYER M5 ;
        RECT  12.336 21.516 12.36 21.6 ;
    END
  END o[71]
  PIN o[72]
    DIRECTION OUTPUT ;
    USE SIGNAL ;
    PORT
      LAYER M5 ;
        RECT  12.432 21.516 12.456 21.6 ;
    END
  END o[72]
  PIN o[73]
    DIRECTION OUTPUT ;
    USE SIGNAL ;
    PORT
      LAYER M5 ;
        RECT  12.528 21.516 12.552 21.6 ;
    END
  END o[73]
  PIN o[74]
    DIRECTION OUTPUT ;
    USE SIGNAL ;
    PORT
      LAYER M5 ;
        RECT  12.624 21.516 12.648 21.6 ;
    END
  END o[74]
  PIN o[75]
    DIRECTION OUTPUT ;
    USE SIGNAL ;
    PORT
      LAYER M5 ;
        RECT  12.72 21.516 12.744 21.6 ;
    END
  END o[75]
  PIN o[76]
    DIRECTION OUTPUT ;
    USE SIGNAL ;
    PORT
      LAYER M5 ;
        RECT  12.816 21.516 12.84 21.6 ;
    END
  END o[76]
  PIN o[77]
    DIRECTION OUTPUT ;
    USE SIGNAL ;
    PORT
      LAYER M5 ;
        RECT  12.912 21.516 12.936 21.6 ;
    END
  END o[77]
  PIN o[78]
    DIRECTION OUTPUT ;
    USE SIGNAL ;
    PORT
      LAYER M5 ;
        RECT  13.008 21.516 13.032 21.6 ;
    END
  END o[78]
  PIN o[79]
    DIRECTION OUTPUT ;
    USE SIGNAL ;
    PORT
      LAYER M5 ;
        RECT  13.104 21.516 13.128 21.6 ;
    END
  END o[79]
  PIN o[7]
    DIRECTION OUTPUT ;
    USE SIGNAL ;
    PORT
      LAYER M5 ;
        RECT  6.192 21.516 6.216 21.6 ;
    END
  END o[7]
  PIN o[80]
    DIRECTION OUTPUT ;
    USE SIGNAL ;
    PORT
      LAYER M5 ;
        RECT  13.2 21.516 13.224 21.6 ;
    END
  END o[80]
  PIN o[81]
    DIRECTION OUTPUT ;
    USE SIGNAL ;
    PORT
      LAYER M5 ;
        RECT  13.296 21.516 13.32 21.6 ;
    END
  END o[81]
  PIN o[82]
    DIRECTION OUTPUT ;
    USE SIGNAL ;
    PORT
      LAYER M5 ;
        RECT  13.392 21.516 13.416 21.6 ;
    END
  END o[82]
  PIN o[83]
    DIRECTION OUTPUT ;
    USE SIGNAL ;
    PORT
      LAYER M5 ;
        RECT  13.488 21.516 13.512 21.6 ;
    END
  END o[83]
  PIN o[84]
    DIRECTION OUTPUT ;
    USE SIGNAL ;
    PORT
      LAYER M5 ;
        RECT  13.584 21.516 13.608 21.6 ;
    END
  END o[84]
  PIN o[85]
    DIRECTION OUTPUT ;
    USE SIGNAL ;
    PORT
      LAYER M5 ;
        RECT  13.68 21.516 13.704 21.6 ;
    END
  END o[85]
  PIN o[86]
    DIRECTION OUTPUT ;
    USE SIGNAL ;
    PORT
      LAYER M5 ;
        RECT  13.776 21.516 13.8 21.6 ;
    END
  END o[86]
  PIN o[87]
    DIRECTION OUTPUT ;
    USE SIGNAL ;
    PORT
      LAYER M5 ;
        RECT  13.872 21.516 13.896 21.6 ;
    END
  END o[87]
  PIN o[88]
    DIRECTION OUTPUT ;
    USE SIGNAL ;
    PORT
      LAYER M5 ;
        RECT  13.968 21.516 13.992 21.6 ;
    END
  END o[88]
  PIN o[89]
    DIRECTION OUTPUT ;
    USE SIGNAL ;
    PORT
      LAYER M5 ;
        RECT  14.064 21.516 14.088 21.6 ;
    END
  END o[89]
  PIN o[8]
    DIRECTION OUTPUT ;
    USE SIGNAL ;
    PORT
      LAYER M5 ;
        RECT  6.288 21.516 6.312 21.6 ;
    END
  END o[8]
  PIN o[90]
    DIRECTION OUTPUT ;
    USE SIGNAL ;
    PORT
      LAYER M5 ;
        RECT  14.16 21.516 14.184 21.6 ;
    END
  END o[90]
  PIN o[91]
    DIRECTION OUTPUT ;
    USE SIGNAL ;
    PORT
      LAYER M5 ;
        RECT  14.256 21.516 14.28 21.6 ;
    END
  END o[91]
  PIN o[92]
    DIRECTION OUTPUT ;
    USE SIGNAL ;
    PORT
      LAYER M5 ;
        RECT  14.352 21.516 14.376 21.6 ;
    END
  END o[92]
  PIN o[93]
    DIRECTION OUTPUT ;
    USE SIGNAL ;
    PORT
      LAYER M5 ;
        RECT  14.448 21.516 14.472 21.6 ;
    END
  END o[93]
  PIN o[94]
    DIRECTION OUTPUT ;
    USE SIGNAL ;
    PORT
      LAYER M5 ;
        RECT  14.544 21.516 14.568 21.6 ;
    END
  END o[94]
  PIN o[95]
    DIRECTION OUTPUT ;
    USE SIGNAL ;
    PORT
      LAYER M5 ;
        RECT  14.64 21.516 14.664 21.6 ;
    END
  END o[95]
  PIN o[96]
    DIRECTION OUTPUT ;
    USE SIGNAL ;
    PORT
      LAYER M5 ;
        RECT  14.736 21.516 14.76 21.6 ;
    END
  END o[96]
  PIN o[97]
    DIRECTION OUTPUT ;
    USE SIGNAL ;
    PORT
      LAYER M5 ;
        RECT  14.832 21.516 14.856 21.6 ;
    END
  END o[97]
  PIN o[98]
    DIRECTION OUTPUT ;
    USE SIGNAL ;
    PORT
      LAYER M5 ;
        RECT  14.928 21.516 14.952 21.6 ;
    END
  END o[98]
  PIN o[99]
    DIRECTION OUTPUT ;
    USE SIGNAL ;
    PORT
      LAYER M5 ;
        RECT  15.024 21.516 15.048 21.6 ;
    END
  END o[99]
  PIN o[9]
    DIRECTION OUTPUT ;
    USE SIGNAL ;
    PORT
      LAYER M5 ;
        RECT  6.384 21.516 6.408 21.6 ;
    END
  END o[9]
  PIN rfi
    DIRECTION INPUT ;
    USE SIGNAL ;
    PORT
      LAYER M5 ;
        RECT  4.56 0 4.584 0.084 ;
    END
  END rfi
  PIN rfo
    DIRECTION OUTPUT ;
    USE SIGNAL ;
    PORT
      LAYER M5 ;
        RECT  5.328 21.516 5.352 21.6 ;
    END
  END rfo
  PIN rs
    DIRECTION INPUT ;
    USE SIGNAL ;
    PORT
      LAYER M4 ;
        RECT  0 9.456 0.084 9.48 ;
    END
  END rs
  PIN rso
    DIRECTION OUTPUT ;
    USE SIGNAL ;
    PORT
      LAYER M5 ;
        RECT  5.424 21.516 5.448 21.6 ;
    END
  END rso
  PIN VDD
    DIRECTION INOUT ;
    USE POWER ;
    PORT
      LAYER M5 ;
        RECT  18.792 2.151 18.912 19.449 ;
        RECT  16.092 2.151 16.212 19.449 ;
        RECT  13.392 2.151 13.512 19.449 ;
        RECT  10.692 2.151 10.812 19.449 ;
        RECT  7.992 2.151 8.112 19.449 ;
        RECT  5.292 2.151 5.412 19.449 ;
        RECT  2.592 2.151 2.712 19.449 ;
    END
  END VDD
  PIN VSS
    DIRECTION INOUT ;
    USE GROUND ;
    PORT
      LAYER M5 ;
        RECT  18.6 2.137 18.72 19.463 ;
        RECT  15.9 2.137 16.02 19.463 ;
        RECT  13.2 2.137 13.32 19.463 ;
        RECT  10.5 2.137 10.62 19.463 ;
        RECT  7.8 2.137 7.92 19.463 ;
        RECT  5.1 2.137 5.22 19.463 ;
        RECT  2.4 2.137 2.52 19.463 ;
    END
  END VSS
  # OT_OBS_CLOSED layer=M5 d_um=1.536 added=14
  OBS
    LAYER RVTN ;
     RECT  2.16 2.16 19.44 2.295 ;
     RECT  2.16 2.565 19.44 2.835 ;
     RECT  2.16 3.105 19.44 3.375 ;
     RECT  2.16 3.645 19.44 3.915 ;
     RECT  2.16 4.185 19.44 4.455 ;
     RECT  2.16 4.725 19.44 4.995 ;
     RECT  2.16 5.265 19.44 5.535 ;
     RECT  2.16 5.805 19.44 6.075 ;
     RECT  2.16 6.345 19.44 6.615 ;
     RECT  2.16 6.885 19.44 7.155 ;
     RECT  2.16 7.425 19.44 7.695 ;
     RECT  2.16 7.965 19.44 8.235 ;
     RECT  2.16 8.505 19.44 8.775 ;
     RECT  2.16 9.045 19.44 9.315 ;
     RECT  2.16 9.585 19.44 9.855 ;
     RECT  2.16 10.125 19.44 10.395 ;
     RECT  2.16 10.665 19.44 10.935 ;
     RECT  2.16 11.205 19.44 11.475 ;
     RECT  2.16 11.745 19.44 12.015 ;
     RECT  2.16 12.285 19.44 12.555 ;
     RECT  2.16 12.825 19.44 13.095 ;
     RECT  2.16 13.365 19.44 13.635 ;
     RECT  2.16 13.905 19.44 14.175 ;
     RECT  2.16 14.445 19.44 14.715 ;
     RECT  2.16 14.985 19.44 15.255 ;
     RECT  2.16 15.525 19.44 15.795 ;
     RECT  2.16 16.065 19.44 16.335 ;
     RECT  2.16 16.605 19.44 16.875 ;
     RECT  2.16 17.145 19.44 17.415 ;
     RECT  2.16 17.685 19.44 17.955 ;
     RECT  2.16 18.225 19.44 18.495 ;
     RECT  2.16 18.765 19.44 19.035 ;
     RECT  2.16 19.305 19.44 19.44 ;
    LAYER RVTP ;
     RECT  2.16 2.295 19.44 2.565 ;
     RECT  2.16 2.835 19.44 3.105 ;
     RECT  2.16 3.375 19.44 3.645 ;
     RECT  2.16 3.915 19.44 4.185 ;
     RECT  2.16 4.455 19.44 4.725 ;
     RECT  2.16 4.995 19.44 5.265 ;
     RECT  2.16 5.535 19.44 5.805 ;
     RECT  2.16 6.075 19.44 6.345 ;
     RECT  2.16 6.615 19.44 6.885 ;
     RECT  2.16 7.155 19.44 7.425 ;
     RECT  2.16 7.695 19.44 7.965 ;
     RECT  2.16 8.235 19.44 8.505 ;
     RECT  2.16 8.775 19.44 9.045 ;
     RECT  2.16 9.315 19.44 9.585 ;
     RECT  2.16 9.855 19.44 10.125 ;
     RECT  2.16 10.395 19.44 10.665 ;
     RECT  2.16 10.935 19.44 11.205 ;
     RECT  2.16 11.475 19.44 11.745 ;
     RECT  2.16 12.015 19.44 12.285 ;
     RECT  2.16 12.555 19.44 12.825 ;
     RECT  2.16 13.095 19.44 13.365 ;
     RECT  2.16 13.635 19.44 13.905 ;
     RECT  2.16 14.175 19.44 14.445 ;
     RECT  2.16 14.715 19.44 14.985 ;
     RECT  2.16 15.255 19.44 15.525 ;
     RECT  2.16 15.795 19.44 16.065 ;
     RECT  2.16 16.335 19.44 16.605 ;
     RECT  2.16 16.875 19.44 17.145 ;
     RECT  2.16 17.415 19.44 17.685 ;
     RECT  2.16 17.955 19.44 18.225 ;
     RECT  2.16 18.495 19.44 18.765 ;
     RECT  2.16 19.035 19.44 19.305 ;
    LAYER M1 ;
     RECT  2.16 2.151 19.44 19.449 ;
    LAYER M2 ;
     RECT  2.16 2.151 3.631 19.449 ;
     RECT  3.631 2.106 4.199 19.449 ;
     RECT  4.199 2.151 12.667 19.449 ;
     RECT  12.667 2.106 15.035 19.449 ;
     RECT  15.035 2.151 17.095 19.449 ;
     RECT  17.095 2.106 19.139 19.449 ;
     RECT  19.139 2.151 19.44 19.449 ;
    LAYER M3 ;
     RECT  6.84 0.571 6.858 0.619 ;
     RECT  10.98 0.571 10.998 1.147 ;
     RECT  14.076 1.147 14.094 1.675 ;
     RECT  4.176 0.571 4.194 1.723 ;
     RECT  6.84 0.619 7.002 1.723 ;
     RECT  10.98 1.147 11.466 1.723 ;
     RECT  14.076 1.675 14.13 1.723 ;
     RECT  16.308 1.675 16.326 1.723 ;
     RECT  17.064 1.627 17.082 1.723 ;
     RECT  19.08 0.571 19.098 1.723 ;
     RECT  3.924 1.723 4.518 1.771 ;
     RECT  6.84 1.723 8.91 1.771 ;
     RECT  10.188 1.723 14.382 1.771 ;
     RECT  15.696 1.723 17.082 1.771 ;
     RECT  17.856 1.723 19.098 1.771 ;
     RECT  3.924 1.771 4.95 1.819 ;
     RECT  10.188 1.771 14.454 2.101 ;
     RECT  15.696 1.771 19.098 2.101 ;
     RECT  3.6 1.819 4.95 2.143 ;
     RECT  6.84 1.771 9.126 2.191 ;
     RECT  10.188 2.101 19.134 2.191 ;
     RECT  3.6 2.143 5.205 2.263 ;
     RECT  6.768 2.191 19.134 2.263 ;
     RECT  2.415 2.143 2.505 2.413 ;
     RECT  3.6 2.263 5.238 2.413 ;
     RECT  6.768 2.263 19.206 2.605 ;
     RECT  3.6 2.413 5.397 2.641 ;
     RECT  3.6 2.641 5.526 2.731 ;
     RECT  6.48 2.605 19.206 2.731 ;
     RECT  3.6 2.731 19.206 3.181 ;
     RECT  3.6 3.181 19.386 3.569 ;
     RECT  3.888 3.569 19.386 4.685 ;
     RECT  3.996 4.685 19.386 5.189 ;
     RECT  4.248 5.189 19.386 5.495 ;
     RECT  4.392 5.495 19.386 6.583 ;
     RECT  3.78 6.583 19.386 6.961 ;
     RECT  2.415 2.413 2.697 7.195 ;
     RECT  3.744 6.961 19.386 7.357 ;
     RECT  2.415 7.195 2.826 7.501 ;
     RECT  3.6 7.357 19.386 7.501 ;
     RECT  2.415 7.501 19.386 7.655 ;
     RECT  2.415 7.655 2.697 9.451 ;
     RECT  3.78 7.655 19.386 9.545 ;
     RECT  2.304 9.451 2.697 9.625 ;
     RECT  2.304 9.625 3.006 9.779 ;
     RECT  2.304 9.779 2.79 9.815 ;
     RECT  3.78 9.545 19.278 9.917 ;
     RECT  3.78 9.917 19.17 10.193 ;
     RECT  3.78 10.193 19.062 11.281 ;
     RECT  3.78 11.281 19.206 11.821 ;
     RECT  3.78 11.821 19.314 13.631 ;
     RECT  3.78 13.631 19.17 14.521 ;
     RECT  3.78 14.521 19.314 14.813 ;
     RECT  3.78 14.813 19.206 16.303 ;
     RECT  2.415 9.815 2.697 17.077 ;
     RECT  2.415 17.077 2.79 17.491 ;
     RECT  3.78 16.303 19.278 17.491 ;
     RECT  2.415 17.491 19.278 18.149 ;
     RECT  2.415 18.149 19.242 18.221 ;
     RECT  2.415 18.221 19.206 18.491 ;
     RECT  2.415 18.491 19.17 18.833 ;
     RECT  3.924 18.833 19.17 19.229 ;
     RECT  2.415 18.833 3.114 19.265 ;
     RECT  4.032 19.229 6.678 19.301 ;
     RECT  7.452 19.229 12.222 19.301 ;
     RECT  13.14 19.229 16.005 19.301 ;
     RECT  16.776 19.229 18.705 19.301 ;
     RECT  7.668 19.301 12.222 19.325 ;
     RECT  2.415 19.265 2.97 19.337 ;
     RECT  4.032 19.301 5.706 19.337 ;
     RECT  7.668 19.325 11.25 19.373 ;
     RECT  14.76 19.301 16.005 19.373 ;
     RECT  2.415 19.337 2.505 19.457 ;
     RECT  13.14 19.301 14.022 19.457 ;
     RECT  15.3 19.373 16.005 19.457 ;
     RECT  18 19.301 18.705 19.457 ;
     RECT  7.668 19.373 9.306 19.565 ;
     RECT  13.14 19.457 13.158 19.565 ;
     RECT  16.884 19.301 17.046 19.565 ;
     RECT  8.136 19.565 9.306 19.613 ;
     RECT  10.368 19.373 10.674 19.613 ;
     RECT  14.004 19.457 14.022 19.661 ;
     RECT  4.176 19.337 5.706 19.949 ;
     RECT  6.588 19.301 6.678 19.997 ;
     RECT  8.712 19.613 9.306 19.997 ;
     RECT  12.204 19.325 12.222 19.997 ;
     RECT  16.92 19.565 17.046 19.997 ;
     RECT  4.176 19.949 5.634 20.045 ;
     RECT  4.824 20.045 5.634 20.525 ;
     RECT  6.588 19.997 6.606 20.525 ;
     RECT  15.3 19.457 15.894 20.525 ;
     RECT  16.92 19.997 16.938 20.525 ;
     RECT  4.824 20.525 5.562 20.573 ;
     RECT  8.712 19.997 9.126 20.573 ;
     RECT  10.656 19.613 10.674 20.573 ;
     RECT  8.712 20.573 8.73 21.067 ;
     RECT  15.408 20.525 15.894 21.163 ;
     RECT  13.572 21.211 13.59 21.259 ;
     RECT  12.636 21.211 12.654 21.307 ;
     RECT  12.636 21.307 12.726 21.389 ;
     RECT  8.244 21.067 8.73 21.437 ;
     RECT  15.408 21.163 16.398 21.437 ;
     RECT  18 19.457 18.018 21.437 ;
     RECT  5.544 20.573 5.562 21.485 ;
     RECT  8.316 21.437 8.73 21.485 ;
     RECT  12.708 21.389 12.726 21.485 ;
     RECT  13.572 21.259 14.094 21.485 ;
     RECT  15.876 21.437 16.398 21.485 ;
    LAYER M4 ;
     RECT  0.084 9.36 0.133 9.384 ;
     RECT  0.06 9.384 0.133 9.456 ;
     RECT  0.084 9.456 0.133 9.48 ;
     RECT  0.133 9.024 2.408 9.48 ;
     RECT  2.408 2.148 2.512 19.452 ;
     RECT  2.512 2.418 2.704 19.182 ;
     RECT  3.589 1.824 3.781 1.848 ;
     RECT  3.781 1.728 4.061 1.848 ;
     RECT  2.704 9.024 4.237 9.048 ;
     RECT  4.165 0.576 4.249 0.6 ;
     RECT  4.165 20.016 4.273 20.04 ;
     RECT  2.704 7.2 4.417 7.224 ;
     RECT  4.061 1.728 4.529 1.8 ;
     RECT  3.985 17.376 4.549 17.4 ;
     RECT  2.704 18.768 4.549 18.792 ;
     RECT  4.453 5.184 4.633 5.208 ;
     RECT  4.273 19.968 4.813 20.04 ;
     RECT  4.549 17.376 4.849 18.792 ;
     RECT  4.813 19.968 4.849 20.568 ;
     RECT  4.529 1.776 4.961 1.8 ;
     RECT  4.777 3.408 5.108 3.432 ;
     RECT  4.633 4.56 5.108 5.208 ;
     RECT  4.417 7.2 5.108 7.992 ;
     RECT  4.237 9.024 5.108 9.528 ;
     RECT  4.849 17.376 5.108 20.568 ;
     RECT  5.108 2.148 5.212 20.568 ;
     RECT  5.212 2.418 5.317 20.568 ;
     RECT  5.317 2.418 5.404 21.48 ;
     RECT  5.404 7.968 5.555 9.912 ;
     RECT  5.555 7.968 5.573 9.864 ;
     RECT  5.404 19.92 5.573 21.48 ;
     RECT  5.404 3.264 5.651 6.264 ;
     RECT  5.404 14.832 5.681 17.688 ;
     RECT  5.573 19.92 5.717 20.52 ;
     RECT  5.681 14.832 6.005 17.4 ;
     RECT  5.404 18.768 6.035 18.888 ;
     RECT  6.005 15.36 6.329 17.4 ;
     RECT  6.035 18.768 6.419 18.84 ;
     RECT  5.651 3.264 6.433 3.816 ;
     RECT  5.651 5.04 6.545 6.264 ;
     RECT  5.717 19.968 6.617 20.52 ;
     RECT  6.329 17.184 6.709 17.4 ;
     RECT  6.641 12.48 6.725 12.504 ;
     RECT  6.709 17.184 6.803 18.312 ;
     RECT  6.803 18.24 6.806 18.312 ;
     RECT  6.617 19.968 6.899 19.992 ;
     RECT  6.829 0.576 6.973 0.6 ;
     RECT  6.853 1.728 7.037 1.752 ;
     RECT  7.045 14.544 7.141 14.568 ;
     RECT  6.973 0.576 7.283 0.648 ;
     RECT  7.141 14.208 7.325 14.568 ;
     RECT  6.433 3.216 7.333 3.816 ;
     RECT  7.333 2.88 7.34 3.864 ;
     RECT  6.545 5.04 7.34 5.736 ;
     RECT  6.329 15.984 7.429 16.2 ;
     RECT  6.803 17.184 7.429 17.208 ;
     RECT  7.34 2.88 7.585 5.736 ;
     RECT  6.805 6.816 7.585 6.84 ;
     RECT  7.325 14.016 7.613 14.568 ;
     RECT  7.429 15.984 7.613 17.208 ;
     RECT  7.585 2.88 7.621 6.84 ;
     RECT  5.573 7.968 7.621 9.048 ;
     RECT  7.573 0.192 7.669 0.216 ;
     RECT  7.037 1.728 7.808 1.848 ;
     RECT  7.621 2.88 7.808 9.048 ;
     RECT  7.525 12.912 7.808 12.936 ;
     RECT  7.613 14.016 7.808 17.208 ;
     RECT  6.806 18.24 7.808 18.264 ;
     RECT  7.657 19.536 7.808 19.56 ;
     RECT  7.669 0.144 7.859 0.216 ;
     RECT  7.808 1.728 7.909 19.56 ;
     RECT  7.813 20.544 7.909 20.568 ;
     RECT  7.859 0.192 7.955 0.216 ;
     RECT  7.909 1.728 8.005 20.568 ;
     RECT  8.005 1.728 8.104 21.192 ;
     RECT  8.104 15.504 8.165 21.192 ;
     RECT  8.165 19.92 8.189 21.192 ;
     RECT  8.189 19.92 8.242 21.432 ;
     RECT  8.104 1.728 8.417 1.848 ;
     RECT  8.165 15.504 8.489 18.84 ;
     RECT  8.104 3.36 8.525 9.048 ;
     RECT  8.104 13.632 8.561 14.28 ;
     RECT  8.489 15.984 8.597 18.84 ;
     RECT  8.242 19.92 8.741 21.48 ;
     RECT  8.417 1.728 8.921 1.8 ;
     RECT  8.921 1.776 9.137 1.8 ;
     RECT  8.597 16.512 9.137 18.84 ;
     RECT  8.741 19.92 9.137 20.568 ;
     RECT  8.561 14.208 9.157 14.28 ;
     RECT  9.137 16.512 9.245 17.208 ;
     RECT  8.104 10.608 9.341 11.736 ;
     RECT  9.253 13.056 9.341 13.08 ;
     RECT  9.137 19.92 9.491 19.992 ;
     RECT  9.137 18.24 9.529 18.84 ;
     RECT  9.157 14.208 9.637 14.808 ;
     RECT  8.525 3.408 9.877 9.048 ;
     RECT  9.341 10.608 9.877 13.08 ;
     RECT  9.637 14.208 9.925 14.856 ;
     RECT  9.877 3.408 9.973 13.08 ;
     RECT  10.021 1.728 10.213 1.752 ;
     RECT  9.925 14.208 10.309 15.384 ;
     RECT  9.245 16.56 10.309 17.208 ;
     RECT  10.261 0.192 10.357 0.216 ;
     RECT  10.261 21.408 10.357 21.432 ;
     RECT  10.357 21.312 10.451 21.432 ;
     RECT  10.213 1.728 10.465 1.848 ;
     RECT  9.973 2.832 10.465 13.08 ;
     RECT  10.465 1.728 10.508 13.08 ;
     RECT  10.309 14.208 10.508 17.208 ;
     RECT  9.529 18.24 10.508 19.608 ;
     RECT  10.357 0.144 10.547 0.216 ;
     RECT  10.451 21.312 10.547 21.336 ;
     RECT  10.547 0.192 10.643 0.216 ;
     RECT  10.508 1.728 10.645 19.608 ;
     RECT  10.645 1.728 10.739 20.568 ;
     RECT  10.739 1.728 10.804 20.52 ;
     RECT  10.804 18.768 10.835 20.52 ;
     RECT  10.969 0.576 11.053 0.6 ;
     RECT  10.804 14.832 11.369 17.688 ;
     RECT  10.804 3.648 11.411 13.464 ;
     RECT  10.804 1.728 11.437 2.28 ;
     RECT  11.437 1.152 11.521 2.28 ;
     RECT  10.835 18.768 11.549 19.368 ;
     RECT  11.369 14.832 11.837 17.208 ;
     RECT  11.411 3.648 11.909 9.144 ;
     RECT  11.411 10.608 11.909 13.464 ;
     RECT  11.837 14.832 11.941 14.856 ;
     RECT  10.835 20.496 12.188 20.52 ;
     RECT  11.549 18.768 12.221 18.888 ;
     RECT  12.188 19.968 12.515 20.52 ;
     RECT  11.521 1.728 12.517 2.28 ;
     RECT  11.909 3.984 12.553 9.144 ;
     RECT  11.909 10.608 12.553 13.224 ;
     RECT  12.517 21.216 12.581 21.288 ;
     RECT  12.581 21.216 12.658 21.384 ;
     RECT  11.941 14.496 12.901 14.856 ;
     RECT  11.837 15.936 12.901 17.208 ;
     RECT  12.517 1.728 12.997 2.904 ;
     RECT  12.553 3.984 12.997 13.224 ;
     RECT  12.901 14.496 12.997 17.208 ;
     RECT  12.221 18.24 13.129 18.888 ;
     RECT  12.997 1.728 13.208 17.208 ;
     RECT  13.129 18.24 13.208 19.656 ;
     RECT  13.381 0.336 13.429 0.36 ;
     RECT  13.208 1.728 13.504 19.656 ;
     RECT  12.658 21.216 13.601 21.48 ;
     RECT  13.429 0.144 13.619 0.36 ;
     RECT  13.504 1.728 13.637 10.296 ;
     RECT  13.504 12.48 13.709 14.28 ;
     RECT  13.709 12.528 13.753 14.28 ;
     RECT  13.504 15.888 14.033 19.656 ;
     RECT  13.637 1.728 14.065 1.8 ;
     RECT  13.601 21.264 14.105 21.48 ;
     RECT  13.637 2.832 14.249 10.296 ;
     RECT  14.065 1.152 14.509 1.8 ;
     RECT  14.249 2.88 14.569 10.296 ;
     RECT  13.504 11.376 14.569 11.4 ;
     RECT  14.033 15.888 14.723 19.368 ;
     RECT  13.753 14.256 14.725 14.28 ;
     RECT  14.509 1.152 14.771 1.176 ;
     RECT  14.723 15.888 14.788 17.976 ;
     RECT  14.723 18.96 14.789 19.368 ;
     RECT  14.788 15.84 14.797 17.976 ;
     RECT  14.797 17.568 14.861 17.976 ;
     RECT  14.105 21.264 14.917 21.432 ;
     RECT  14.569 2.88 14.929 11.4 ;
     RECT  13.753 12.528 14.929 13.08 ;
     RECT  14.797 15.84 15.013 16.536 ;
     RECT  14.929 2.88 15.205 13.08 ;
     RECT  14.725 14.208 15.205 14.28 ;
     RECT  14.917 20.496 15.329 21.432 ;
     RECT  15.329 21.072 15.397 21.432 ;
     RECT  15.205 2.88 15.433 14.28 ;
     RECT  15.013 15.36 15.493 16.536 ;
     RECT  15.433 2.832 15.733 14.28 ;
     RECT  15.493 15.312 15.733 16.536 ;
     RECT  15.685 1.728 15.908 1.752 ;
     RECT  15.733 2.832 15.908 16.536 ;
     RECT  14.861 17.616 15.908 17.976 ;
     RECT  14.789 18.96 15.908 18.984 ;
     RECT  15.908 1.728 15.973 19.452 ;
     RECT  15.973 1.68 16.213 19.452 ;
     RECT  16.213 1.68 16.309 19.56 ;
     RECT  15.733 0.144 16.355 0.168 ;
     RECT  15.397 21.072 16.444 21.48 ;
     RECT  16.309 1.152 16.547 19.56 ;
     RECT  16.547 1.632 16.553 19.56 ;
     RECT  16.553 13.056 16.645 19.56 ;
     RECT  16.444 21.072 16.645 21.432 ;
     RECT  16.645 13.056 16.733 21.432 ;
     RECT  16.733 13.104 16.949 21.432 ;
     RECT  16.553 1.632 17.057 12.072 ;
     RECT  17.057 1.632 17.093 12.024 ;
     RECT  17.093 1.728 17.453 12.024 ;
     RECT  16.949 13.104 17.633 19.992 ;
     RECT  17.633 17.568 17.651 19.992 ;
     RECT  16.949 21.408 18.029 21.432 ;
     RECT  18.229 0.144 18.325 0.168 ;
     RECT  18.325 0.144 18.421 0.216 ;
     RECT  17.633 13.104 18.421 16.392 ;
     RECT  17.453 1.728 18.569 11.928 ;
     RECT  18.569 2.016 18.608 11.928 ;
     RECT  18.421 13.056 18.608 16.392 ;
     RECT  17.651 17.568 18.608 19.452 ;
     RECT  18.421 0.144 18.611 0.264 ;
     RECT  18.611 0.192 18.707 0.264 ;
     RECT  18.608 2.016 18.712 19.452 ;
     RECT  18.707 0.24 18.803 0.264 ;
     RECT  18.712 2.016 18.904 19.182 ;
     RECT  18.904 3.024 18.965 7.368 ;
     RECT  18.904 9.216 18.965 10.728 ;
     RECT  18.904 2.016 19.001 2.04 ;
     RECT  18.965 5.184 19.001 7.368 ;
     RECT  18.904 16.368 19.037 16.392 ;
     RECT  18.965 9.216 19.043 9.912 ;
     RECT  18.904 17.664 19.043 18.216 ;
     RECT  19.001 5.472 19.073 7.368 ;
     RECT  18.904 14.784 19.073 14.856 ;
     RECT  18.949 0.576 19.109 0.6 ;
     RECT  18.965 3.024 19.109 4.152 ;
     RECT  19.073 6.384 19.109 7.368 ;
     RECT  19.109 3.024 19.117 4.008 ;
     RECT  19.117 3.024 19.145 3.048 ;
     RECT  19.109 7.344 19.145 7.368 ;
     RECT  19.043 9.888 19.289 9.912 ;
     RECT  19.043 18.192 19.331 18.216 ;
     RECT  19.073 14.784 19.369 14.808 ;
    LAYER M5 ;
     RECT  3.816 0.016 3.888 0.084 ;
     RECT  3.912 0.016 3.984 0.084 ;
     RECT  4.008 0.016 4.08 0.084 ;
     RECT  4.104 0.016 4.176 0.084 ;
     RECT  4.2 0.016 4.272 0.084 ;
     RECT  4.296 0.016 4.368 0.084 ;
     RECT  4.392 0.016 4.464 0.084 ;
     RECT  4.488 0.016 4.56 0.084 ;
     RECT  3.792 0.084 4.584 1.763 ;
     RECT  6.888 0.016 6.96 0.084 ;
     RECT  6.984 0.016 7.056 0.084 ;
     RECT  7.08 0.016 7.152 0.084 ;
     RECT  7.176 0.016 7.248 0.084 ;
     RECT  7.272 0.016 7.344 0.084 ;
     RECT  7.368 0.016 7.44 0.084 ;
     RECT  7.464 0.016 7.536 0.084 ;
     RECT  7.56 0.016 7.632 0.084 ;
     RECT  7.656 0.016 7.728 0.084 ;
     RECT  7.752 0.016 7.824 0.084 ;
     RECT  7.848 0.016 7.92 0.084 ;
     RECT  7.944 0.016 8.016 0.084 ;
     RECT  8.04 0.016 8.112 0.084 ;
     RECT  8.136 0.016 8.208 0.084 ;
     RECT  8.232 0.016 8.304 0.084 ;
     RECT  8.328 0.016 8.4 0.084 ;
     RECT  8.424 0.016 8.496 0.084 ;
     RECT  8.52 0.016 8.592 0.084 ;
     RECT  8.616 0.016 8.688 0.084 ;
     RECT  8.712 0.016 8.784 0.084 ;
     RECT  8.808 0.016 8.88 0.084 ;
     RECT  8.904 0.016 8.976 0.084 ;
     RECT  9 0.016 9.072 0.084 ;
     RECT  9.096 0.016 9.168 0.084 ;
     RECT  9.192 0.016 9.264 0.084 ;
     RECT  9.288 0.016 9.36 0.084 ;
     RECT  9.384 0.016 9.456 0.084 ;
     RECT  9.48 0.016 9.552 0.084 ;
     RECT  9.576 0.016 9.648 0.084 ;
     RECT  9.672 0.016 9.744 0.084 ;
     RECT  9.768 0.016 9.84 0.084 ;
     RECT  9.864 0.016 9.936 0.084 ;
     RECT  9.96 0.016 10.032 0.084 ;
     RECT  10.056 0.016 10.128 0.084 ;
     RECT  10.152 0.016 10.224 0.084 ;
     RECT  10.248 0.016 10.32 0.084 ;
     RECT  10.344 0.016 10.416 0.084 ;
     RECT  10.44 0.016 10.512 0.084 ;
     RECT  10.536 0.016 10.608 0.084 ;
     RECT  10.632 0.016 10.704 0.084 ;
     RECT  10.728 0.016 10.8 0.084 ;
     RECT  10.824 0.016 10.896 0.084 ;
     RECT  10.92 0.016 10.992 0.084 ;
     RECT  11.016 0.016 11.088 0.084 ;
     RECT  11.112 0.016 11.184 0.084 ;
     RECT  11.208 0.016 11.28 0.084 ;
     RECT  11.304 0.016 11.376 0.084 ;
     RECT  11.4 0.016 11.472 0.084 ;
     RECT  11.496 0.016 11.568 0.084 ;
     RECT  11.592 0.016 11.664 0.084 ;
     RECT  11.688 0.016 11.76 0.084 ;
     RECT  11.784 0.016 11.856 0.084 ;
     RECT  11.88 0.016 11.952 0.084 ;
     RECT  11.976 0.016 12.048 0.084 ;
     RECT  12.072 0.016 12.144 0.084 ;
     RECT  12.168 0.016 12.24 0.084 ;
     RECT  12.264 0.016 12.336 0.084 ;
     RECT  12.36 0.016 12.432 0.084 ;
     RECT  12.456 0.016 12.528 0.084 ;
     RECT  12.552 0.016 12.624 0.084 ;
     RECT  12.648 0.016 12.72 0.084 ;
     RECT  12.744 0.016 12.816 0.084 ;
     RECT  12.84 0.016 12.912 0.084 ;
     RECT  12.936 0.016 13.008 0.084 ;
     RECT  13.032 0.016 13.104 0.084 ;
     RECT  13.128 0.016 13.2 0.084 ;
     RECT  13.224 0.016 13.296 0.084 ;
     RECT  13.32 0.016 13.392 0.084 ;
     RECT  13.416 0.016 13.488 0.084 ;
     RECT  13.512 0.016 13.584 0.084 ;
     RECT  13.608 0.016 13.68 0.084 ;
     RECT  13.704 0.016 13.776 0.084 ;
     RECT  13.8 0.016 13.872 0.084 ;
     RECT  13.896 0.016 13.968 0.084 ;
     RECT  13.992 0.016 14.064 0.084 ;
     RECT  14.088 0.016 14.16 0.084 ;
     RECT  14.184 0.016 14.256 0.084 ;
     RECT  14.28 0.016 14.352 0.084 ;
     RECT  14.376 0.016 14.448 0.084 ;
     RECT  14.472 0.016 14.544 0.084 ;
     RECT  14.568 0.016 14.64 0.084 ;
     RECT  14.664 0.016 14.736 0.084 ;
     RECT  14.76 0.016 14.832 0.084 ;
     RECT  14.856 0.016 14.928 0.084 ;
     RECT  14.952 0.016 15.024 0.084 ;
     RECT  15.048 0.016 15.12 0.084 ;
     RECT  15.144 0.016 15.216 0.084 ;
     RECT  15.24 0.016 15.312 0.084 ;
     RECT  15.336 0.016 15.408 0.084 ;
     RECT  15.432 0.016 15.504 0.084 ;
     RECT  15.528 0.016 15.6 0.084 ;
     RECT  15.624 0.016 15.696 0.084 ;
     RECT  15.72 0.016 15.792 0.084 ;
     RECT  15.816 0.016 15.888 0.084 ;
     RECT  15.912 0.016 15.984 0.084 ;
     RECT  16.008 0.016 16.08 0.084 ;
     RECT  16.104 0.016 16.176 0.084 ;
     RECT  16.2 0.016 16.272 0.084 ;
     RECT  16.296 0.016 16.368 0.084 ;
     RECT  16.392 0.016 16.464 0.084 ;
     RECT  16.488 0.016 16.56 0.084 ;
     RECT  16.584 0.016 16.656 0.084 ;
     RECT  16.68 0.016 16.752 0.084 ;
     RECT  16.776 0.016 16.848 0.084 ;
     RECT  16.872 0.016 16.944 0.084 ;
     RECT  16.968 0.016 17.04 0.084 ;
     RECT  17.064 0.016 17.136 0.084 ;
     RECT  17.16 0.016 17.232 0.084 ;
     RECT  17.256 0.016 17.328 0.084 ;
     RECT  17.352 0.016 17.424 0.084 ;
     RECT  17.448 0.016 17.52 0.084 ;
     RECT  17.544 0.016 17.616 0.084 ;
     RECT  17.64 0.016 17.712 0.084 ;
     RECT  17.736 0.016 17.808 0.084 ;
     RECT  17.832 0.016 17.904 0.084 ;
     RECT  17.928 0.016 18 0.084 ;
     RECT  18.024 0.016 18.096 0.084 ;
     RECT  18.12 0.016 18.192 0.084 ;
     RECT  18.216 0.016 18.288 0.084 ;
     RECT  18.312 0.016 18.384 0.084 ;
     RECT  18.408 0.016 18.48 0.084 ;
     RECT  18.504 0.016 18.576 0.084 ;
     RECT  18.6 0.016 18.672 0.084 ;
     RECT  18.696 0.016 18.768 0.084 ;
     RECT  18.792 0.016 18.864 0.084 ;
     RECT  18.888 0.016 18.96 0.084 ;
     RECT  18.984 0.016 19.056 0.084 ;
     RECT  6.864 0.084 19.08 1.763 ;
     RECT  3.888 1.763 4.584 1.811 ;
     RECT  7.056 1.763 19.08 1.811 ;
     RECT  3.888 1.811 4.008 1.859 ;
     RECT  7.056 1.811 10.824 1.859 ;
     RECT  7.344 1.859 10.824 2.051 ;
     RECT  2.4 2.137 2.52 2.151 ;
     RECT  5.1 2.137 5.22 2.151 ;
     RECT  11.856 1.811 19.08 2.291 ;
     RECT  7.344 2.051 10.812 2.915 ;
     RECT  12.528 2.291 19.08 2.915 ;
     RECT  5.1 2.151 5.412 3.685 ;
     RECT  7.536 2.915 10.812 4.019 ;
     RECT  12.624 2.915 19.08 4.019 ;
     RECT  7.536 4.019 8.112 4.501 ;
     RECT  7.392 4.501 8.112 5.077 ;
     RECT  9.168 4.019 10.812 5.077 ;
     RECT  12.864 4.019 18.912 5.125 ;
     RECT  12.048 5.125 18.912 5.219 ;
     RECT  7.392 5.077 10.812 5.221 ;
     RECT  12.048 5.219 17.16 5.411 ;
     RECT  5.1 3.685 5.736 5.747 ;
     RECT  6.72 5.221 10.812 6.229 ;
     RECT  6.72 6.229 11.064 6.277 ;
     RECT  6.72 6.277 11.592 7.333 ;
     RECT  12.864 5.411 17.16 7.333 ;
     RECT  6.72 7.333 17.16 7.381 ;
     RECT  18.192 5.219 18.912 7.381 ;
     RECT  5.1 5.747 5.412 7.957 ;
     RECT  6.72 7.381 18.912 7.957 ;
     RECT  5.1 7.957 18.912 8.723 ;
     RECT  6.72 8.723 18.912 9.205 ;
     RECT  0.144 9.013 0.168 9.395 ;
     RECT  6.72 9.205 19.032 10.979 ;
     RECT  6.72 10.979 14.712 11.941 ;
     RECT  15.9 10.979 19.032 11.941 ;
     RECT  6.72 11.941 19.032 12.469 ;
     RECT  6.672 12.469 19.032 14.773 ;
     RECT  5.1 8.723 5.544 14.821 ;
     RECT  6.672 14.773 19.32 14.821 ;
     RECT  5.1 14.821 19.32 17.653 ;
     RECT  4.848 17.653 19.32 18.227 ;
     RECT  4.848 18.227 18.912 18.325 ;
     RECT  2.4 2.151 2.712 19.449 ;
     RECT  4.56 18.325 18.912 19.449 ;
     RECT  2.4 19.449 2.52 19.463 ;
     RECT  4.56 19.449 18.72 19.463 ;
     RECT  4.56 19.463 17.736 21.516 ;
     RECT  4.584 21.516 4.656 21.584 ;
     RECT  4.68 21.516 4.752 21.584 ;
     RECT  4.776 21.516 4.848 21.584 ;
     RECT  4.872 21.516 4.944 21.584 ;
     RECT  4.968 21.516 5.04 21.584 ;
     RECT  5.064 21.516 5.136 21.584 ;
     RECT  5.16 21.516 5.232 21.584 ;
     RECT  5.256 21.516 5.328 21.584 ;
     RECT  5.352 21.516 5.424 21.584 ;
     RECT  5.448 21.516 5.52 21.584 ;
     RECT  5.544 21.516 5.616 21.584 ;
     RECT  5.64 21.516 5.712 21.584 ;
     RECT  5.736 21.516 5.808 21.584 ;
     RECT  5.832 21.516 5.904 21.584 ;
     RECT  5.928 21.516 6 21.584 ;
     RECT  6.024 21.516 6.096 21.584 ;
     RECT  6.12 21.516 6.192 21.584 ;
     RECT  6.216 21.516 6.288 21.584 ;
     RECT  6.312 21.516 6.384 21.584 ;
     RECT  6.408 21.516 6.48 21.584 ;
     RECT  6.504 21.516 6.576 21.584 ;
     RECT  6.6 21.516 6.672 21.584 ;
     RECT  6.696 21.516 6.768 21.584 ;
     RECT  6.792 21.516 6.864 21.584 ;
     RECT  6.888 21.516 6.96 21.584 ;
     RECT  6.984 21.516 7.056 21.584 ;
     RECT  7.08 21.516 7.152 21.584 ;
     RECT  7.176 21.516 7.248 21.584 ;
     RECT  7.272 21.516 7.344 21.584 ;
     RECT  7.368 21.516 7.44 21.584 ;
     RECT  7.464 21.516 7.536 21.584 ;
     RECT  7.56 21.516 7.632 21.584 ;
     RECT  7.656 21.516 7.728 21.584 ;
     RECT  7.752 21.516 7.824 21.584 ;
     RECT  7.848 21.516 7.92 21.584 ;
     RECT  7.944 21.516 8.016 21.584 ;
     RECT  8.04 21.516 8.112 21.584 ;
     RECT  8.136 21.516 8.208 21.584 ;
     RECT  8.232 21.516 8.304 21.584 ;
     RECT  8.328 21.516 8.4 21.584 ;
     RECT  8.424 21.516 8.496 21.584 ;
     RECT  8.52 21.516 8.592 21.584 ;
     RECT  8.616 21.516 8.688 21.584 ;
     RECT  8.712 21.516 8.784 21.584 ;
     RECT  8.808 21.516 8.88 21.584 ;
     RECT  8.904 21.516 8.976 21.584 ;
     RECT  9 21.516 9.072 21.584 ;
     RECT  9.096 21.516 9.168 21.584 ;
     RECT  9.192 21.516 9.264 21.584 ;
     RECT  9.288 21.516 9.36 21.584 ;
     RECT  9.384 21.516 9.456 21.584 ;
     RECT  9.48 21.516 9.552 21.584 ;
     RECT  9.576 21.516 9.648 21.584 ;
     RECT  9.672 21.516 9.744 21.584 ;
     RECT  9.768 21.516 9.84 21.584 ;
     RECT  9.864 21.516 9.936 21.584 ;
     RECT  9.96 21.516 10.032 21.584 ;
     RECT  10.056 21.516 10.128 21.584 ;
     RECT  10.152 21.516 10.224 21.584 ;
     RECT  10.248 21.516 10.32 21.584 ;
     RECT  10.344 21.516 10.416 21.584 ;
     RECT  10.44 21.516 10.512 21.584 ;
     RECT  10.536 21.516 10.608 21.584 ;
     RECT  10.632 21.516 10.704 21.584 ;
     RECT  10.728 21.516 10.8 21.584 ;
     RECT  10.824 21.516 10.896 21.584 ;
     RECT  10.92 21.516 10.992 21.584 ;
     RECT  11.016 21.516 11.088 21.584 ;
     RECT  11.112 21.516 11.184 21.584 ;
     RECT  11.208 21.516 11.28 21.584 ;
     RECT  11.304 21.516 11.376 21.584 ;
     RECT  11.4 21.516 11.472 21.584 ;
     RECT  11.496 21.516 11.568 21.584 ;
     RECT  11.592 21.516 11.664 21.584 ;
     RECT  11.688 21.516 11.76 21.584 ;
     RECT  11.784 21.516 11.856 21.584 ;
     RECT  11.88 21.516 11.952 21.584 ;
     RECT  11.976 21.516 12.048 21.584 ;
     RECT  12.072 21.516 12.144 21.584 ;
     RECT  12.168 21.516 12.24 21.584 ;
     RECT  12.264 21.516 12.336 21.584 ;
     RECT  12.36 21.516 12.432 21.584 ;
     RECT  12.456 21.516 12.528 21.584 ;
     RECT  12.552 21.516 12.624 21.584 ;
     RECT  12.648 21.516 12.72 21.584 ;
     RECT  12.744 21.516 12.816 21.584 ;
     RECT  12.84 21.516 12.912 21.584 ;
     RECT  12.936 21.516 13.008 21.584 ;
     RECT  13.032 21.516 13.104 21.584 ;
     RECT  13.128 21.516 13.2 21.584 ;
     RECT  13.224 21.516 13.296 21.584 ;
     RECT  13.32 21.516 13.392 21.584 ;
     RECT  13.416 21.516 13.488 21.584 ;
     RECT  13.512 21.516 13.584 21.584 ;
     RECT  13.608 21.516 13.68 21.584 ;
     RECT  13.704 21.516 13.776 21.584 ;
     RECT  13.8 21.516 13.872 21.584 ;
     RECT  13.896 21.516 13.968 21.584 ;
     RECT  13.992 21.516 14.064 21.584 ;
     RECT  14.088 21.516 14.16 21.584 ;
     RECT  14.184 21.516 14.256 21.584 ;
     RECT  14.28 21.516 14.352 21.584 ;
     RECT  14.376 21.516 14.448 21.584 ;
     RECT  14.472 21.516 14.544 21.584 ;
     RECT  14.568 21.516 14.64 21.584 ;
     RECT  14.664 21.516 14.736 21.584 ;
     RECT  14.76 21.516 14.832 21.584 ;
     RECT  14.856 21.516 14.928 21.584 ;
     RECT  14.952 21.516 15.024 21.584 ;
     RECT  15.048 21.516 15.12 21.584 ;
     RECT  15.144 21.516 15.216 21.584 ;
     RECT  15.24 21.516 15.312 21.584 ;
     RECT  15.336 21.516 15.408 21.584 ;
     RECT  15.432 21.516 15.504 21.584 ;
     RECT  15.528 21.516 15.6 21.584 ;
     RECT  15.624 21.516 15.696 21.584 ;
     RECT  15.72 21.516 15.792 21.584 ;
     RECT  15.816 21.516 15.888 21.584 ;
     RECT  15.912 21.516 15.984 21.584 ;
     RECT  16.008 21.516 16.08 21.584 ;
     RECT  16.104 21.516 16.176 21.584 ;
     RECT  16.2 21.516 16.272 21.584 ;
     RECT  16.296 21.516 16.368 21.584 ;
     RECT  16.392 21.516 16.464 21.584 ;
     RECT  16.488 21.516 16.56 21.584 ;
     RECT  16.584 21.516 16.656 21.584 ;
     RECT  16.68 21.516 16.752 21.584 ;
     RECT  16.776 21.516 16.848 21.584 ;
     RECT  16.872 21.516 16.944 21.584 ;
     RECT  16.968 21.516 17.04 21.584 ;
     RECT  17.064 21.516 17.136 21.584 ;
     RECT  17.16 21.516 17.232 21.584 ;
     RECT  17.256 21.516 17.328 21.584 ;
     RECT  17.352 21.516 17.424 21.584 ;
     RECT  17.448 21.516 17.52 21.584 ;
     RECT  17.544 21.516 17.616 21.584 ;
     RECT  17.64 21.516 17.712 21.584 ;
     RECT  10.824 1.811 11.856 2.051 ;
     RECT  10.812 2.051 11.856 2.291 ;
     RECT  8.112 4.019 9.168 5.077 ;
     RECT  12.624 4.019 12.864 5.125 ;
     RECT  10.812 5.125 12.048 5.411 ;
     RECT  17.16 5.219 18.192 7.381 ;
     RECT  5.736 5.221 6.72 5.747 ;
     RECT  10.812 5.411 12.864 6.229 ;
     RECT  5.412 5.747 6.72 7.957 ;
     RECT  11.064 6.229 12.864 6.277 ;
     RECT  11.592 6.277 12.864 7.333 ;
     RECT  5.544 8.723 6.72 12.469 ;
     RECT  14.712 10.979 15.9 11.941 ;
     RECT  5.544 12.469 6.672 14.821 ;
  END
END hbfd_rly_136_SN_rrfc
END LIBRARY
